VERSION 5.8 ;
BUSBITCHARS "[]" ;
DIVIDERCHAR "/" ;
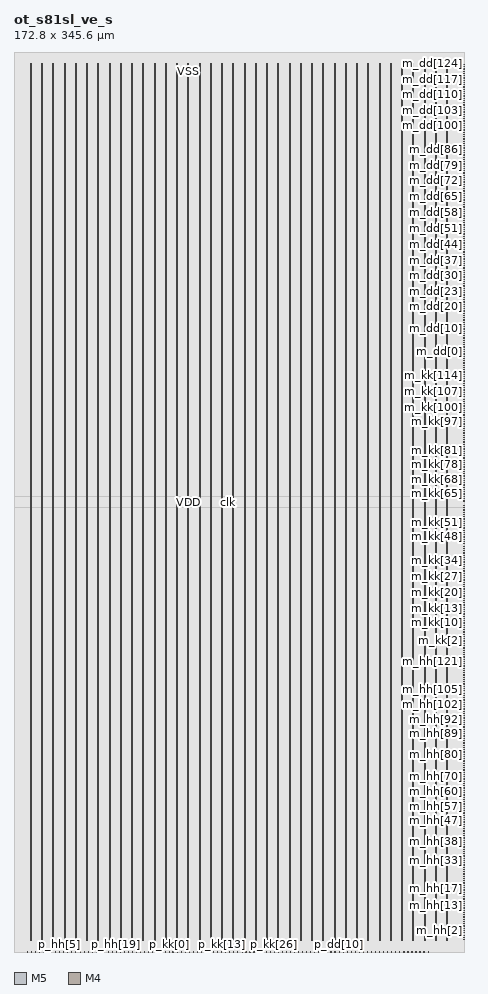
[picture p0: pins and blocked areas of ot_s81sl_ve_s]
MACRO ot_s81sl_ve_s
  CLASS BLOCK ;
  ORIGIN 0 0 ;
  SIZE 172.800 BY 345.600 ;
  PIN clk
    DIRECTION INPUT ;
    USE SIGNAL ;
    PORT
      LAYER M5 ;
        RECT 82.0680 172.5600 82.1160 173.0400 ;
    END
  END clk
  PIN fault
    DIRECTION OUTPUT ;
    USE SIGNAL ;
    PORT
      LAYER M5 ;
        RECT 159.0720 0.0000 159.0960 0.0840 ;
    END
  END fault
  PIN m_dd[0]
    DIRECTION INPUT ;
    USE SIGNAL ;
    PORT
      LAYER M4 ;
        RECT 172.716000 230.496000 172.800000 230.520000 ;
    END
  END m_dd[0]
  PIN m_dd[100]
    DIRECTION INPUT ;
    USE SIGNAL ;
    PORT
      LAYER M4 ;
        RECT 172.716000 317.376000 172.800000 317.400000 ;
    END
  END m_dd[100]
  PIN m_dd[101]
    DIRECTION INPUT ;
    USE SIGNAL ;
    PORT
      LAYER M4 ;
        RECT 172.716000 318.240000 172.800000 318.264000 ;
    END
  END m_dd[101]
  PIN m_dd[102]
    DIRECTION INPUT ;
    USE SIGNAL ;
    PORT
      LAYER M4 ;
        RECT 172.716000 319.104000 172.800000 319.128000 ;
    END
  END m_dd[102]
  PIN m_dd[103]
    DIRECTION INPUT ;
    USE SIGNAL ;
    PORT
      LAYER M4 ;
        RECT 172.716000 319.968000 172.800000 319.992000 ;
    END
  END m_dd[103]
  PIN m_dd[104]
    DIRECTION INPUT ;
    USE SIGNAL ;
    PORT
      LAYER M4 ;
        RECT 172.716000 320.832000 172.800000 320.856000 ;
    END
  END m_dd[104]
  PIN m_dd[105]
    DIRECTION INPUT ;
    USE SIGNAL ;
    PORT
      LAYER M4 ;
        RECT 172.716000 321.696000 172.800000 321.720000 ;
    END
  END m_dd[105]
  PIN m_dd[106]
    DIRECTION INPUT ;
    USE SIGNAL ;
    PORT
      LAYER M4 ;
        RECT 172.716000 322.560000 172.800000 322.584000 ;
    END
  END m_dd[106]
  PIN m_dd[107]
    DIRECTION INPUT ;
    USE SIGNAL ;
    PORT
      LAYER M4 ;
        RECT 172.716000 323.424000 172.800000 323.448000 ;
    END
  END m_dd[107]
  PIN m_dd[108]
    DIRECTION INPUT ;
    USE SIGNAL ;
    PORT
      LAYER M4 ;
        RECT 172.716000 324.288000 172.800000 324.312000 ;
    END
  END m_dd[108]
  PIN m_dd[109]
    DIRECTION INPUT ;
    USE SIGNAL ;
    PORT
      LAYER M4 ;
        RECT 172.716000 325.248000 172.800000 325.272000 ;
    END
  END m_dd[109]
  PIN m_dd[10]
    DIRECTION INPUT ;
    USE SIGNAL ;
    PORT
      LAYER M4 ;
        RECT 172.716000 239.232000 172.800000 239.256000 ;
    END
  END m_dd[10]
  PIN m_dd[110]
    DIRECTION INPUT ;
    USE SIGNAL ;
    PORT
      LAYER M4 ;
        RECT 172.716000 326.112000 172.800000 326.136000 ;
    END
  END m_dd[110]
  PIN m_dd[111]
    DIRECTION INPUT ;
    USE SIGNAL ;
    PORT
      LAYER M4 ;
        RECT 172.716000 326.976000 172.800000 327.000000 ;
    END
  END m_dd[111]
  PIN m_dd[112]
    DIRECTION INPUT ;
    USE SIGNAL ;
    PORT
      LAYER M4 ;
        RECT 172.716000 327.840000 172.800000 327.864000 ;
    END
  END m_dd[112]
  PIN m_dd[113]
    DIRECTION INPUT ;
    USE SIGNAL ;
    PORT
      LAYER M4 ;
        RECT 172.716000 328.704000 172.800000 328.728000 ;
    END
  END m_dd[113]
  PIN m_dd[114]
    DIRECTION INPUT ;
    USE SIGNAL ;
    PORT
      LAYER M4 ;
        RECT 172.716000 329.568000 172.800000 329.592000 ;
    END
  END m_dd[114]
  PIN m_dd[115]
    DIRECTION INPUT ;
    USE SIGNAL ;
    PORT
      LAYER M4 ;
        RECT 172.716000 330.432000 172.800000 330.456000 ;
    END
  END m_dd[115]
  PIN m_dd[116]
    DIRECTION INPUT ;
    USE SIGNAL ;
    PORT
      LAYER M4 ;
        RECT 172.716000 331.296000 172.800000 331.320000 ;
    END
  END m_dd[116]
  PIN m_dd[117]
    DIRECTION INPUT ;
    USE SIGNAL ;
    PORT
      LAYER M4 ;
        RECT 172.716000 332.160000 172.800000 332.184000 ;
    END
  END m_dd[117]
  PIN m_dd[118]
    DIRECTION INPUT ;
    USE SIGNAL ;
    PORT
      LAYER M4 ;
        RECT 172.716000 333.024000 172.800000 333.048000 ;
    END
  END m_dd[118]
  PIN m_dd[119]
    DIRECTION INPUT ;
    USE SIGNAL ;
    PORT
      LAYER M4 ;
        RECT 172.716000 333.888000 172.800000 333.912000 ;
    END
  END m_dd[119]
  PIN m_dd[11]
    DIRECTION INPUT ;
    USE SIGNAL ;
    PORT
      LAYER M4 ;
        RECT 172.716000 240.096000 172.800000 240.120000 ;
    END
  END m_dd[11]
  PIN m_dd[120]
    DIRECTION INPUT ;
    USE SIGNAL ;
    PORT
      LAYER M4 ;
        RECT 172.716000 334.752000 172.800000 334.776000 ;
    END
  END m_dd[120]
  PIN m_dd[121]
    DIRECTION INPUT ;
    USE SIGNAL ;
    PORT
      LAYER M4 ;
        RECT 172.716000 335.616000 172.800000 335.640000 ;
    END
  END m_dd[121]
  PIN m_dd[122]
    DIRECTION INPUT ;
    USE SIGNAL ;
    PORT
      LAYER M4 ;
        RECT 172.716000 336.480000 172.800000 336.504000 ;
    END
  END m_dd[122]
  PIN m_dd[123]
    DIRECTION INPUT ;
    USE SIGNAL ;
    PORT
      LAYER M4 ;
        RECT 172.716000 337.344000 172.800000 337.368000 ;
    END
  END m_dd[123]
  PIN m_dd[124]
    DIRECTION INPUT ;
    USE SIGNAL ;
    PORT
      LAYER M4 ;
        RECT 172.716000 338.208000 172.800000 338.232000 ;
    END
  END m_dd[124]
  PIN m_dd[125]
    DIRECTION INPUT ;
    USE SIGNAL ;
    PORT
      LAYER M4 ;
        RECT 172.716000 339.072000 172.800000 339.096000 ;
    END
  END m_dd[125]
  PIN m_dd[126]
    DIRECTION INPUT ;
    USE SIGNAL ;
    PORT
      LAYER M4 ;
        RECT 172.716000 339.936000 172.800000 339.960000 ;
    END
  END m_dd[126]
  PIN m_dd[127]
    DIRECTION INPUT ;
    USE SIGNAL ;
    PORT
      LAYER M4 ;
        RECT 172.716000 340.800000 172.800000 340.824000 ;
    END
  END m_dd[127]
  PIN m_dd[12]
    DIRECTION INPUT ;
    USE SIGNAL ;
    PORT
      LAYER M4 ;
        RECT 172.716000 240.960000 172.800000 240.984000 ;
    END
  END m_dd[12]
  PIN m_dd[13]
    DIRECTION INPUT ;
    USE SIGNAL ;
    PORT
      LAYER M4 ;
        RECT 172.716000 241.824000 172.800000 241.848000 ;
    END
  END m_dd[13]
  PIN m_dd[14]
    DIRECTION INPUT ;
    USE SIGNAL ;
    PORT
      LAYER M4 ;
        RECT 172.716000 242.688000 172.800000 242.712000 ;
    END
  END m_dd[14]
  PIN m_dd[15]
    DIRECTION INPUT ;
    USE SIGNAL ;
    PORT
      LAYER M4 ;
        RECT 172.716000 243.552000 172.800000 243.576000 ;
    END
  END m_dd[15]
  PIN m_dd[16]
    DIRECTION INPUT ;
    USE SIGNAL ;
    PORT
      LAYER M4 ;
        RECT 172.716000 244.416000 172.800000 244.440000 ;
    END
  END m_dd[16]
  PIN m_dd[17]
    DIRECTION INPUT ;
    USE SIGNAL ;
    PORT
      LAYER M4 ;
        RECT 172.716000 245.280000 172.800000 245.304000 ;
    END
  END m_dd[17]
  PIN m_dd[18]
    DIRECTION INPUT ;
    USE SIGNAL ;
    PORT
      LAYER M4 ;
        RECT 172.716000 246.144000 172.800000 246.168000 ;
    END
  END m_dd[18]
  PIN m_dd[19]
    DIRECTION INPUT ;
    USE SIGNAL ;
    PORT
      LAYER M4 ;
        RECT 172.716000 247.008000 172.800000 247.032000 ;
    END
  END m_dd[19]
  PIN m_dd[1]
    DIRECTION INPUT ;
    USE SIGNAL ;
    PORT
      LAYER M4 ;
        RECT 172.716000 231.456000 172.800000 231.480000 ;
    END
  END m_dd[1]
  PIN m_dd[20]
    DIRECTION INPUT ;
    USE SIGNAL ;
    PORT
      LAYER M4 ;
        RECT 172.716000 247.872000 172.800000 247.896000 ;
    END
  END m_dd[20]
  PIN m_dd[21]
    DIRECTION INPUT ;
    USE SIGNAL ;
    PORT
      LAYER M4 ;
        RECT 172.716000 248.736000 172.800000 248.760000 ;
    END
  END m_dd[21]
  PIN m_dd[22]
    DIRECTION INPUT ;
    USE SIGNAL ;
    PORT
      LAYER M4 ;
        RECT 172.716000 249.600000 172.800000 249.624000 ;
    END
  END m_dd[22]
  PIN m_dd[23]
    DIRECTION INPUT ;
    USE SIGNAL ;
    PORT
      LAYER M4 ;
        RECT 172.716000 250.560000 172.800000 250.584000 ;
    END
  END m_dd[23]
  PIN m_dd[24]
    DIRECTION INPUT ;
    USE SIGNAL ;
    PORT
      LAYER M4 ;
        RECT 172.716000 251.424000 172.800000 251.448000 ;
    END
  END m_dd[24]
  PIN m_dd[25]
    DIRECTION INPUT ;
    USE SIGNAL ;
    PORT
      LAYER M4 ;
        RECT 172.716000 252.288000 172.800000 252.312000 ;
    END
  END m_dd[25]
  PIN m_dd[26]
    DIRECTION INPUT ;
    USE SIGNAL ;
    PORT
      LAYER M4 ;
        RECT 172.716000 253.152000 172.800000 253.176000 ;
    END
  END m_dd[26]
  PIN m_dd[27]
    DIRECTION INPUT ;
    USE SIGNAL ;
    PORT
      LAYER M4 ;
        RECT 172.716000 254.016000 172.800000 254.040000 ;
    END
  END m_dd[27]
  PIN m_dd[28]
    DIRECTION INPUT ;
    USE SIGNAL ;
    PORT
      LAYER M4 ;
        RECT 172.716000 254.880000 172.800000 254.904000 ;
    END
  END m_dd[28]
  PIN m_dd[29]
    DIRECTION INPUT ;
    USE SIGNAL ;
    PORT
      LAYER M4 ;
        RECT 172.716000 255.744000 172.800000 255.768000 ;
    END
  END m_dd[29]
  PIN m_dd[2]
    DIRECTION INPUT ;
    USE SIGNAL ;
    PORT
      LAYER M4 ;
        RECT 172.716000 232.320000 172.800000 232.344000 ;
    END
  END m_dd[2]
  PIN m_dd[30]
    DIRECTION INPUT ;
    USE SIGNAL ;
    PORT
      LAYER M4 ;
        RECT 172.716000 256.608000 172.800000 256.632000 ;
    END
  END m_dd[30]
  PIN m_dd[31]
    DIRECTION INPUT ;
    USE SIGNAL ;
    PORT
      LAYER M4 ;
        RECT 172.716000 257.472000 172.800000 257.496000 ;
    END
  END m_dd[31]
  PIN m_dd[32]
    DIRECTION INPUT ;
    USE SIGNAL ;
    PORT
      LAYER M4 ;
        RECT 172.716000 258.336000 172.800000 258.360000 ;
    END
  END m_dd[32]
  PIN m_dd[33]
    DIRECTION INPUT ;
    USE SIGNAL ;
    PORT
      LAYER M4 ;
        RECT 172.716000 259.200000 172.800000 259.224000 ;
    END
  END m_dd[33]
  PIN m_dd[34]
    DIRECTION INPUT ;
    USE SIGNAL ;
    PORT
      LAYER M4 ;
        RECT 172.716000 260.064000 172.800000 260.088000 ;
    END
  END m_dd[34]
  PIN m_dd[35]
    DIRECTION INPUT ;
    USE SIGNAL ;
    PORT
      LAYER M4 ;
        RECT 172.716000 260.928000 172.800000 260.952000 ;
    END
  END m_dd[35]
  PIN m_dd[36]
    DIRECTION INPUT ;
    USE SIGNAL ;
    PORT
      LAYER M4 ;
        RECT 172.716000 261.792000 172.800000 261.816000 ;
    END
  END m_dd[36]
  PIN m_dd[37]
    DIRECTION INPUT ;
    USE SIGNAL ;
    PORT
      LAYER M4 ;
        RECT 172.716000 262.656000 172.800000 262.680000 ;
    END
  END m_dd[37]
  PIN m_dd[38]
    DIRECTION INPUT ;
    USE SIGNAL ;
    PORT
      LAYER M4 ;
        RECT 172.716000 263.520000 172.800000 263.544000 ;
    END
  END m_dd[38]
  PIN m_dd[39]
    DIRECTION INPUT ;
    USE SIGNAL ;
    PORT
      LAYER M4 ;
        RECT 172.716000 264.384000 172.800000 264.408000 ;
    END
  END m_dd[39]
  PIN m_dd[3]
    DIRECTION INPUT ;
    USE SIGNAL ;
    PORT
      LAYER M4 ;
        RECT 172.716000 233.184000 172.800000 233.208000 ;
    END
  END m_dd[3]
  PIN m_dd[40]
    DIRECTION INPUT ;
    USE SIGNAL ;
    PORT
      LAYER M4 ;
        RECT 172.716000 265.248000 172.800000 265.272000 ;
    END
  END m_dd[40]
  PIN m_dd[41]
    DIRECTION INPUT ;
    USE SIGNAL ;
    PORT
      LAYER M4 ;
        RECT 172.716000 266.112000 172.800000 266.136000 ;
    END
  END m_dd[41]
  PIN m_dd[42]
    DIRECTION INPUT ;
    USE SIGNAL ;
    PORT
      LAYER M4 ;
        RECT 172.716000 266.976000 172.800000 267.000000 ;
    END
  END m_dd[42]
  PIN m_dd[43]
    DIRECTION INPUT ;
    USE SIGNAL ;
    PORT
      LAYER M4 ;
        RECT 172.716000 267.840000 172.800000 267.864000 ;
    END
  END m_dd[43]
  PIN m_dd[44]
    DIRECTION INPUT ;
    USE SIGNAL ;
    PORT
      LAYER M4 ;
        RECT 172.716000 268.800000 172.800000 268.824000 ;
    END
  END m_dd[44]
  PIN m_dd[45]
    DIRECTION INPUT ;
    USE SIGNAL ;
    PORT
      LAYER M4 ;
        RECT 172.716000 269.664000 172.800000 269.688000 ;
    END
  END m_dd[45]
  PIN m_dd[46]
    DIRECTION INPUT ;
    USE SIGNAL ;
    PORT
      LAYER M4 ;
        RECT 172.716000 270.528000 172.800000 270.552000 ;
    END
  END m_dd[46]
  PIN m_dd[47]
    DIRECTION INPUT ;
    USE SIGNAL ;
    PORT
      LAYER M4 ;
        RECT 172.716000 271.392000 172.800000 271.416000 ;
    END
  END m_dd[47]
  PIN m_dd[48]
    DIRECTION INPUT ;
    USE SIGNAL ;
    PORT
      LAYER M4 ;
        RECT 172.716000 272.256000 172.800000 272.280000 ;
    END
  END m_dd[48]
  PIN m_dd[49]
    DIRECTION INPUT ;
    USE SIGNAL ;
    PORT
      LAYER M4 ;
        RECT 172.716000 273.120000 172.800000 273.144000 ;
    END
  END m_dd[49]
  PIN m_dd[4]
    DIRECTION INPUT ;
    USE SIGNAL ;
    PORT
      LAYER M4 ;
        RECT 172.716000 234.048000 172.800000 234.072000 ;
    END
  END m_dd[4]
  PIN m_dd[50]
    DIRECTION INPUT ;
    USE SIGNAL ;
    PORT
      LAYER M4 ;
        RECT 172.716000 273.984000 172.800000 274.008000 ;
    END
  END m_dd[50]
  PIN m_dd[51]
    DIRECTION INPUT ;
    USE SIGNAL ;
    PORT
      LAYER M4 ;
        RECT 172.716000 274.848000 172.800000 274.872000 ;
    END
  END m_dd[51]
  PIN m_dd[52]
    DIRECTION INPUT ;
    USE SIGNAL ;
    PORT
      LAYER M4 ;
        RECT 172.716000 275.712000 172.800000 275.736000 ;
    END
  END m_dd[52]
  PIN m_dd[53]
    DIRECTION INPUT ;
    USE SIGNAL ;
    PORT
      LAYER M4 ;
        RECT 172.716000 276.576000 172.800000 276.600000 ;
    END
  END m_dd[53]
  PIN m_dd[54]
    DIRECTION INPUT ;
    USE SIGNAL ;
    PORT
      LAYER M4 ;
        RECT 172.716000 277.440000 172.800000 277.464000 ;
    END
  END m_dd[54]
  PIN m_dd[55]
    DIRECTION INPUT ;
    USE SIGNAL ;
    PORT
      LAYER M4 ;
        RECT 172.716000 278.304000 172.800000 278.328000 ;
    END
  END m_dd[55]
  PIN m_dd[56]
    DIRECTION INPUT ;
    USE SIGNAL ;
    PORT
      LAYER M4 ;
        RECT 172.716000 279.168000 172.800000 279.192000 ;
    END
  END m_dd[56]
  PIN m_dd[57]
    DIRECTION INPUT ;
    USE SIGNAL ;
    PORT
      LAYER M4 ;
        RECT 172.716000 280.032000 172.800000 280.056000 ;
    END
  END m_dd[57]
  PIN m_dd[58]
    DIRECTION INPUT ;
    USE SIGNAL ;
    PORT
      LAYER M4 ;
        RECT 172.716000 280.896000 172.800000 280.920000 ;
    END
  END m_dd[58]
  PIN m_dd[59]
    DIRECTION INPUT ;
    USE SIGNAL ;
    PORT
      LAYER M4 ;
        RECT 172.716000 281.760000 172.800000 281.784000 ;
    END
  END m_dd[59]
  PIN m_dd[5]
    DIRECTION INPUT ;
    USE SIGNAL ;
    PORT
      LAYER M4 ;
        RECT 172.716000 234.912000 172.800000 234.936000 ;
    END
  END m_dd[5]
  PIN m_dd[60]
    DIRECTION INPUT ;
    USE SIGNAL ;
    PORT
      LAYER M4 ;
        RECT 172.716000 282.624000 172.800000 282.648000 ;
    END
  END m_dd[60]
  PIN m_dd[61]
    DIRECTION INPUT ;
    USE SIGNAL ;
    PORT
      LAYER M4 ;
        RECT 172.716000 283.488000 172.800000 283.512000 ;
    END
  END m_dd[61]
  PIN m_dd[62]
    DIRECTION INPUT ;
    USE SIGNAL ;
    PORT
      LAYER M4 ;
        RECT 172.716000 284.352000 172.800000 284.376000 ;
    END
  END m_dd[62]
  PIN m_dd[63]
    DIRECTION INPUT ;
    USE SIGNAL ;
    PORT
      LAYER M4 ;
        RECT 172.716000 285.216000 172.800000 285.240000 ;
    END
  END m_dd[63]
  PIN m_dd[64]
    DIRECTION INPUT ;
    USE SIGNAL ;
    PORT
      LAYER M4 ;
        RECT 172.716000 286.080000 172.800000 286.104000 ;
    END
  END m_dd[64]
  PIN m_dd[65]
    DIRECTION INPUT ;
    USE SIGNAL ;
    PORT
      LAYER M4 ;
        RECT 172.716000 286.944000 172.800000 286.968000 ;
    END
  END m_dd[65]
  PIN m_dd[66]
    DIRECTION INPUT ;
    USE SIGNAL ;
    PORT
      LAYER M4 ;
        RECT 172.716000 287.904000 172.800000 287.928000 ;
    END
  END m_dd[66]
  PIN m_dd[67]
    DIRECTION INPUT ;
    USE SIGNAL ;
    PORT
      LAYER M4 ;
        RECT 172.716000 288.768000 172.800000 288.792000 ;
    END
  END m_dd[67]
  PIN m_dd[68]
    DIRECTION INPUT ;
    USE SIGNAL ;
    PORT
      LAYER M4 ;
        RECT 172.716000 289.632000 172.800000 289.656000 ;
    END
  END m_dd[68]
  PIN m_dd[69]
    DIRECTION INPUT ;
    USE SIGNAL ;
    PORT
      LAYER M4 ;
        RECT 172.716000 290.496000 172.800000 290.520000 ;
    END
  END m_dd[69]
  PIN m_dd[6]
    DIRECTION INPUT ;
    USE SIGNAL ;
    PORT
      LAYER M4 ;
        RECT 172.716000 235.776000 172.800000 235.800000 ;
    END
  END m_dd[6]
  PIN m_dd[70]
    DIRECTION INPUT ;
    USE SIGNAL ;
    PORT
      LAYER M4 ;
        RECT 172.716000 291.360000 172.800000 291.384000 ;
    END
  END m_dd[70]
  PIN m_dd[71]
    DIRECTION INPUT ;
    USE SIGNAL ;
    PORT
      LAYER M4 ;
        RECT 172.716000 292.224000 172.800000 292.248000 ;
    END
  END m_dd[71]
  PIN m_dd[72]
    DIRECTION INPUT ;
    USE SIGNAL ;
    PORT
      LAYER M4 ;
        RECT 172.716000 293.088000 172.800000 293.112000 ;
    END
  END m_dd[72]
  PIN m_dd[73]
    DIRECTION INPUT ;
    USE SIGNAL ;
    PORT
      LAYER M4 ;
        RECT 172.716000 293.952000 172.800000 293.976000 ;
    END
  END m_dd[73]
  PIN m_dd[74]
    DIRECTION INPUT ;
    USE SIGNAL ;
    PORT
      LAYER M4 ;
        RECT 172.716000 294.816000 172.800000 294.840000 ;
    END
  END m_dd[74]
  PIN m_dd[75]
    DIRECTION INPUT ;
    USE SIGNAL ;
    PORT
      LAYER M4 ;
        RECT 172.716000 295.680000 172.800000 295.704000 ;
    END
  END m_dd[75]
  PIN m_dd[76]
    DIRECTION INPUT ;
    USE SIGNAL ;
    PORT
      LAYER M4 ;
        RECT 172.716000 296.544000 172.800000 296.568000 ;
    END
  END m_dd[76]
  PIN m_dd[77]
    DIRECTION INPUT ;
    USE SIGNAL ;
    PORT
      LAYER M4 ;
        RECT 172.716000 297.408000 172.800000 297.432000 ;
    END
  END m_dd[77]
  PIN m_dd[78]
    DIRECTION INPUT ;
    USE SIGNAL ;
    PORT
      LAYER M4 ;
        RECT 172.716000 298.272000 172.800000 298.296000 ;
    END
  END m_dd[78]
  PIN m_dd[79]
    DIRECTION INPUT ;
    USE SIGNAL ;
    PORT
      LAYER M4 ;
        RECT 172.716000 299.136000 172.800000 299.160000 ;
    END
  END m_dd[79]
  PIN m_dd[7]
    DIRECTION INPUT ;
    USE SIGNAL ;
    PORT
      LAYER M4 ;
        RECT 172.716000 236.640000 172.800000 236.664000 ;
    END
  END m_dd[7]
  PIN m_dd[80]
    DIRECTION INPUT ;
    USE SIGNAL ;
    PORT
      LAYER M4 ;
        RECT 172.716000 300.000000 172.800000 300.024000 ;
    END
  END m_dd[80]
  PIN m_dd[81]
    DIRECTION INPUT ;
    USE SIGNAL ;
    PORT
      LAYER M4 ;
        RECT 172.716000 300.864000 172.800000 300.888000 ;
    END
  END m_dd[81]
  PIN m_dd[82]
    DIRECTION INPUT ;
    USE SIGNAL ;
    PORT
      LAYER M4 ;
        RECT 172.716000 301.728000 172.800000 301.752000 ;
    END
  END m_dd[82]
  PIN m_dd[83]
    DIRECTION INPUT ;
    USE SIGNAL ;
    PORT
      LAYER M4 ;
        RECT 172.716000 302.592000 172.800000 302.616000 ;
    END
  END m_dd[83]
  PIN m_dd[84]
    DIRECTION INPUT ;
    USE SIGNAL ;
    PORT
      LAYER M4 ;
        RECT 172.716000 303.456000 172.800000 303.480000 ;
    END
  END m_dd[84]
  PIN m_dd[85]
    DIRECTION INPUT ;
    USE SIGNAL ;
    PORT
      LAYER M4 ;
        RECT 172.716000 304.320000 172.800000 304.344000 ;
    END
  END m_dd[85]
  PIN m_dd[86]
    DIRECTION INPUT ;
    USE SIGNAL ;
    PORT
      LAYER M4 ;
        RECT 172.716000 305.184000 172.800000 305.208000 ;
    END
  END m_dd[86]
  PIN m_dd[87]
    DIRECTION INPUT ;
    USE SIGNAL ;
    PORT
      LAYER M4 ;
        RECT 172.716000 306.048000 172.800000 306.072000 ;
    END
  END m_dd[87]
  PIN m_dd[88]
    DIRECTION INPUT ;
    USE SIGNAL ;
    PORT
      LAYER M4 ;
        RECT 172.716000 307.008000 172.800000 307.032000 ;
    END
  END m_dd[88]
  PIN m_dd[89]
    DIRECTION INPUT ;
    USE SIGNAL ;
    PORT
      LAYER M4 ;
        RECT 172.716000 307.872000 172.800000 307.896000 ;
    END
  END m_dd[89]
  PIN m_dd[8]
    DIRECTION INPUT ;
    USE SIGNAL ;
    PORT
      LAYER M4 ;
        RECT 172.716000 237.504000 172.800000 237.528000 ;
    END
  END m_dd[8]
  PIN m_dd[90]
    DIRECTION INPUT ;
    USE SIGNAL ;
    PORT
      LAYER M4 ;
        RECT 172.716000 308.736000 172.800000 308.760000 ;
    END
  END m_dd[90]
  PIN m_dd[91]
    DIRECTION INPUT ;
    USE SIGNAL ;
    PORT
      LAYER M4 ;
        RECT 172.716000 309.600000 172.800000 309.624000 ;
    END
  END m_dd[91]
  PIN m_dd[92]
    DIRECTION INPUT ;
    USE SIGNAL ;
    PORT
      LAYER M4 ;
        RECT 172.716000 310.464000 172.800000 310.488000 ;
    END
  END m_dd[92]
  PIN m_dd[93]
    DIRECTION INPUT ;
    USE SIGNAL ;
    PORT
      LAYER M4 ;
        RECT 172.716000 311.328000 172.800000 311.352000 ;
    END
  END m_dd[93]
  PIN m_dd[94]
    DIRECTION INPUT ;
    USE SIGNAL ;
    PORT
      LAYER M4 ;
        RECT 172.716000 312.192000 172.800000 312.216000 ;
    END
  END m_dd[94]
  PIN m_dd[95]
    DIRECTION INPUT ;
    USE SIGNAL ;
    PORT
      LAYER M4 ;
        RECT 172.716000 313.056000 172.800000 313.080000 ;
    END
  END m_dd[95]
  PIN m_dd[96]
    DIRECTION INPUT ;
    USE SIGNAL ;
    PORT
      LAYER M4 ;
        RECT 172.716000 313.920000 172.800000 313.944000 ;
    END
  END m_dd[96]
  PIN m_dd[97]
    DIRECTION INPUT ;
    USE SIGNAL ;
    PORT
      LAYER M4 ;
        RECT 172.716000 314.784000 172.800000 314.808000 ;
    END
  END m_dd[97]
  PIN m_dd[98]
    DIRECTION INPUT ;
    USE SIGNAL ;
    PORT
      LAYER M4 ;
        RECT 172.716000 315.648000 172.800000 315.672000 ;
    END
  END m_dd[98]
  PIN m_dd[99]
    DIRECTION INPUT ;
    USE SIGNAL ;
    PORT
      LAYER M4 ;
        RECT 172.716000 316.512000 172.800000 316.536000 ;
    END
  END m_dd[99]
  PIN m_dd[9]
    DIRECTION INPUT ;
    USE SIGNAL ;
    PORT
      LAYER M4 ;
        RECT 172.716000 238.368000 172.800000 238.392000 ;
    END
  END m_dd[9]
  PIN m_hh[0]
    DIRECTION INPUT ;
    USE SIGNAL ;
    PORT
      LAYER M4 ;
        RECT 172.716000 6.432000 172.800000 6.456000 ;
    END
  END m_hh[0]
  PIN m_hh[100]
    DIRECTION INPUT ;
    USE SIGNAL ;
    PORT
      LAYER M4 ;
        RECT 172.716000 93.312000 172.800000 93.336000 ;
    END
  END m_hh[100]
  PIN m_hh[101]
    DIRECTION INPUT ;
    USE SIGNAL ;
    PORT
      LAYER M4 ;
        RECT 172.716000 94.176000 172.800000 94.200000 ;
    END
  END m_hh[101]
  PIN m_hh[102]
    DIRECTION INPUT ;
    USE SIGNAL ;
    PORT
      LAYER M4 ;
        RECT 172.716000 95.040000 172.800000 95.064000 ;
    END
  END m_hh[102]
  PIN m_hh[103]
    DIRECTION INPUT ;
    USE SIGNAL ;
    PORT
      LAYER M4 ;
        RECT 172.716000 95.904000 172.800000 95.928000 ;
    END
  END m_hh[103]
  PIN m_hh[104]
    DIRECTION INPUT ;
    USE SIGNAL ;
    PORT
      LAYER M4 ;
        RECT 172.716000 96.768000 172.800000 96.792000 ;
    END
  END m_hh[104]
  PIN m_hh[105]
    DIRECTION INPUT ;
    USE SIGNAL ;
    PORT
      LAYER M4 ;
        RECT 172.716000 97.632000 172.800000 97.656000 ;
    END
  END m_hh[105]
  PIN m_hh[106]
    DIRECTION INPUT ;
    USE SIGNAL ;
    PORT
      LAYER M4 ;
        RECT 172.716000 98.496000 172.800000 98.520000 ;
    END
  END m_hh[106]
  PIN m_hh[107]
    DIRECTION INPUT ;
    USE SIGNAL ;
    PORT
      LAYER M4 ;
        RECT 172.716000 99.360000 172.800000 99.384000 ;
    END
  END m_hh[107]
  PIN m_hh[108]
    DIRECTION INPUT ;
    USE SIGNAL ;
    PORT
      LAYER M4 ;
        RECT 172.716000 100.320000 172.800000 100.344000 ;
    END
  END m_hh[108]
  PIN m_hh[109]
    DIRECTION INPUT ;
    USE SIGNAL ;
    PORT
      LAYER M4 ;
        RECT 172.716000 101.184000 172.800000 101.208000 ;
    END
  END m_hh[109]
  PIN m_hh[10]
    DIRECTION INPUT ;
    USE SIGNAL ;
    PORT
      LAYER M4 ;
        RECT 172.716000 15.168000 172.800000 15.192000 ;
    END
  END m_hh[10]
  PIN m_hh[110]
    DIRECTION INPUT ;
    USE SIGNAL ;
    PORT
      LAYER M4 ;
        RECT 172.716000 102.048000 172.800000 102.072000 ;
    END
  END m_hh[110]
  PIN m_hh[111]
    DIRECTION INPUT ;
    USE SIGNAL ;
    PORT
      LAYER M4 ;
        RECT 172.716000 102.912000 172.800000 102.936000 ;
    END
  END m_hh[111]
  PIN m_hh[112]
    DIRECTION INPUT ;
    USE SIGNAL ;
    PORT
      LAYER M4 ;
        RECT 172.716000 103.776000 172.800000 103.800000 ;
    END
  END m_hh[112]
  PIN m_hh[113]
    DIRECTION INPUT ;
    USE SIGNAL ;
    PORT
      LAYER M4 ;
        RECT 172.716000 104.640000 172.800000 104.664000 ;
    END
  END m_hh[113]
  PIN m_hh[114]
    DIRECTION INPUT ;
    USE SIGNAL ;
    PORT
      LAYER M4 ;
        RECT 172.716000 105.504000 172.800000 105.528000 ;
    END
  END m_hh[114]
  PIN m_hh[115]
    DIRECTION INPUT ;
    USE SIGNAL ;
    PORT
      LAYER M4 ;
        RECT 172.716000 106.368000 172.800000 106.392000 ;
    END
  END m_hh[115]
  PIN m_hh[116]
    DIRECTION INPUT ;
    USE SIGNAL ;
    PORT
      LAYER M4 ;
        RECT 172.716000 107.232000 172.800000 107.256000 ;
    END
  END m_hh[116]
  PIN m_hh[117]
    DIRECTION INPUT ;
    USE SIGNAL ;
    PORT
      LAYER M4 ;
        RECT 172.716000 108.096000 172.800000 108.120000 ;
    END
  END m_hh[117]
  PIN m_hh[118]
    DIRECTION INPUT ;
    USE SIGNAL ;
    PORT
      LAYER M4 ;
        RECT 172.716000 108.960000 172.800000 108.984000 ;
    END
  END m_hh[118]
  PIN m_hh[119]
    DIRECTION INPUT ;
    USE SIGNAL ;
    PORT
      LAYER M4 ;
        RECT 172.716000 109.824000 172.800000 109.848000 ;
    END
  END m_hh[119]
  PIN m_hh[11]
    DIRECTION INPUT ;
    USE SIGNAL ;
    PORT
      LAYER M4 ;
        RECT 172.716000 16.032000 172.800000 16.056000 ;
    END
  END m_hh[11]
  PIN m_hh[120]
    DIRECTION INPUT ;
    USE SIGNAL ;
    PORT
      LAYER M4 ;
        RECT 172.716000 110.688000 172.800000 110.712000 ;
    END
  END m_hh[120]
  PIN m_hh[121]
    DIRECTION INPUT ;
    USE SIGNAL ;
    PORT
      LAYER M4 ;
        RECT 172.716000 111.552000 172.800000 111.576000 ;
    END
  END m_hh[121]
  PIN m_hh[122]
    DIRECTION INPUT ;
    USE SIGNAL ;
    PORT
      LAYER M4 ;
        RECT 172.716000 112.416000 172.800000 112.440000 ;
    END
  END m_hh[122]
  PIN m_hh[123]
    DIRECTION INPUT ;
    USE SIGNAL ;
    PORT
      LAYER M4 ;
        RECT 172.716000 113.280000 172.800000 113.304000 ;
    END
  END m_hh[123]
  PIN m_hh[124]
    DIRECTION INPUT ;
    USE SIGNAL ;
    PORT
      LAYER M4 ;
        RECT 172.716000 114.144000 172.800000 114.168000 ;
    END
  END m_hh[124]
  PIN m_hh[125]
    DIRECTION INPUT ;
    USE SIGNAL ;
    PORT
      LAYER M4 ;
        RECT 172.716000 115.008000 172.800000 115.032000 ;
    END
  END m_hh[125]
  PIN m_hh[126]
    DIRECTION INPUT ;
    USE SIGNAL ;
    PORT
      LAYER M4 ;
        RECT 172.716000 115.872000 172.800000 115.896000 ;
    END
  END m_hh[126]
  PIN m_hh[127]
    DIRECTION INPUT ;
    USE SIGNAL ;
    PORT
      LAYER M4 ;
        RECT 172.716000 116.736000 172.800000 116.760000 ;
    END
  END m_hh[127]
  PIN m_hh[12]
    DIRECTION INPUT ;
    USE SIGNAL ;
    PORT
      LAYER M4 ;
        RECT 172.716000 16.896000 172.800000 16.920000 ;
    END
  END m_hh[12]
  PIN m_hh[13]
    DIRECTION INPUT ;
    USE SIGNAL ;
    PORT
      LAYER M4 ;
        RECT 172.716000 17.760000 172.800000 17.784000 ;
    END
  END m_hh[13]
  PIN m_hh[14]
    DIRECTION INPUT ;
    USE SIGNAL ;
    PORT
      LAYER M4 ;
        RECT 172.716000 18.624000 172.800000 18.648000 ;
    END
  END m_hh[14]
  PIN m_hh[15]
    DIRECTION INPUT ;
    USE SIGNAL ;
    PORT
      LAYER M4 ;
        RECT 172.716000 19.488000 172.800000 19.512000 ;
    END
  END m_hh[15]
  PIN m_hh[16]
    DIRECTION INPUT ;
    USE SIGNAL ;
    PORT
      LAYER M4 ;
        RECT 172.716000 20.352000 172.800000 20.376000 ;
    END
  END m_hh[16]
  PIN m_hh[17]
    DIRECTION INPUT ;
    USE SIGNAL ;
    PORT
      LAYER M4 ;
        RECT 172.716000 21.216000 172.800000 21.240000 ;
    END
  END m_hh[17]
  PIN m_hh[18]
    DIRECTION INPUT ;
    USE SIGNAL ;
    PORT
      LAYER M4 ;
        RECT 172.716000 22.080000 172.800000 22.104000 ;
    END
  END m_hh[18]
  PIN m_hh[19]
    DIRECTION INPUT ;
    USE SIGNAL ;
    PORT
      LAYER M4 ;
        RECT 172.716000 22.944000 172.800000 22.968000 ;
    END
  END m_hh[19]
  PIN m_hh[1]
    DIRECTION INPUT ;
    USE SIGNAL ;
    PORT
      LAYER M4 ;
        RECT 172.716000 7.392000 172.800000 7.416000 ;
    END
  END m_hh[1]
  PIN m_hh[20]
    DIRECTION INPUT ;
    USE SIGNAL ;
    PORT
      LAYER M4 ;
        RECT 172.716000 23.808000 172.800000 23.832000 ;
    END
  END m_hh[20]
  PIN m_hh[21]
    DIRECTION INPUT ;
    USE SIGNAL ;
    PORT
      LAYER M4 ;
        RECT 172.716000 24.672000 172.800000 24.696000 ;
    END
  END m_hh[21]
  PIN m_hh[22]
    DIRECTION INPUT ;
    USE SIGNAL ;
    PORT
      LAYER M4 ;
        RECT 172.716000 25.632000 172.800000 25.656000 ;
    END
  END m_hh[22]
  PIN m_hh[23]
    DIRECTION INPUT ;
    USE SIGNAL ;
    PORT
      LAYER M4 ;
        RECT 172.716000 26.496000 172.800000 26.520000 ;
    END
  END m_hh[23]
  PIN m_hh[24]
    DIRECTION INPUT ;
    USE SIGNAL ;
    PORT
      LAYER M4 ;
        RECT 172.716000 27.360000 172.800000 27.384000 ;
    END
  END m_hh[24]
  PIN m_hh[25]
    DIRECTION INPUT ;
    USE SIGNAL ;
    PORT
      LAYER M4 ;
        RECT 172.716000 28.224000 172.800000 28.248000 ;
    END
  END m_hh[25]
  PIN m_hh[26]
    DIRECTION INPUT ;
    USE SIGNAL ;
    PORT
      LAYER M4 ;
        RECT 172.716000 29.088000 172.800000 29.112000 ;
    END
  END m_hh[26]
  PIN m_hh[27]
    DIRECTION INPUT ;
    USE SIGNAL ;
    PORT
      LAYER M4 ;
        RECT 172.716000 29.952000 172.800000 29.976000 ;
    END
  END m_hh[27]
  PIN m_hh[28]
    DIRECTION INPUT ;
    USE SIGNAL ;
    PORT
      LAYER M4 ;
        RECT 172.716000 30.816000 172.800000 30.840000 ;
    END
  END m_hh[28]
  PIN m_hh[29]
    DIRECTION INPUT ;
    USE SIGNAL ;
    PORT
      LAYER M4 ;
        RECT 172.716000 31.680000 172.800000 31.704000 ;
    END
  END m_hh[29]
  PIN m_hh[2]
    DIRECTION INPUT ;
    USE SIGNAL ;
    PORT
      LAYER M4 ;
        RECT 172.716000 8.256000 172.800000 8.280000 ;
    END
  END m_hh[2]
  PIN m_hh[30]
    DIRECTION INPUT ;
    USE SIGNAL ;
    PORT
      LAYER M4 ;
        RECT 172.716000 32.544000 172.800000 32.568000 ;
    END
  END m_hh[30]
  PIN m_hh[31]
    DIRECTION INPUT ;
    USE SIGNAL ;
    PORT
      LAYER M4 ;
        RECT 172.716000 33.408000 172.800000 33.432000 ;
    END
  END m_hh[31]
  PIN m_hh[32]
    DIRECTION INPUT ;
    USE SIGNAL ;
    PORT
      LAYER M4 ;
        RECT 172.716000 34.272000 172.800000 34.296000 ;
    END
  END m_hh[32]
  PIN m_hh[33]
    DIRECTION INPUT ;
    USE SIGNAL ;
    PORT
      LAYER M4 ;
        RECT 172.716000 35.136000 172.800000 35.160000 ;
    END
  END m_hh[33]
  PIN m_hh[34]
    DIRECTION INPUT ;
    USE SIGNAL ;
    PORT
      LAYER M4 ;
        RECT 172.716000 36.000000 172.800000 36.024000 ;
    END
  END m_hh[34]
  PIN m_hh[35]
    DIRECTION INPUT ;
    USE SIGNAL ;
    PORT
      LAYER M4 ;
        RECT 172.716000 36.864000 172.800000 36.888000 ;
    END
  END m_hh[35]
  PIN m_hh[36]
    DIRECTION INPUT ;
    USE SIGNAL ;
    PORT
      LAYER M4 ;
        RECT 172.716000 37.728000 172.800000 37.752000 ;
    END
  END m_hh[36]
  PIN m_hh[37]
    DIRECTION INPUT ;
    USE SIGNAL ;
    PORT
      LAYER M4 ;
        RECT 172.716000 38.592000 172.800000 38.616000 ;
    END
  END m_hh[37]
  PIN m_hh[38]
    DIRECTION INPUT ;
    USE SIGNAL ;
    PORT
      LAYER M4 ;
        RECT 172.716000 39.456000 172.800000 39.480000 ;
    END
  END m_hh[38]
  PIN m_hh[39]
    DIRECTION INPUT ;
    USE SIGNAL ;
    PORT
      LAYER M4 ;
        RECT 172.716000 40.320000 172.800000 40.344000 ;
    END
  END m_hh[39]
  PIN m_hh[3]
    DIRECTION INPUT ;
    USE SIGNAL ;
    PORT
      LAYER M4 ;
        RECT 172.716000 9.120000 172.800000 9.144000 ;
    END
  END m_hh[3]
  PIN m_hh[40]
    DIRECTION INPUT ;
    USE SIGNAL ;
    PORT
      LAYER M4 ;
        RECT 172.716000 41.184000 172.800000 41.208000 ;
    END
  END m_hh[40]
  PIN m_hh[41]
    DIRECTION INPUT ;
    USE SIGNAL ;
    PORT
      LAYER M4 ;
        RECT 172.716000 42.048000 172.800000 42.072000 ;
    END
  END m_hh[41]
  PIN m_hh[42]
    DIRECTION INPUT ;
    USE SIGNAL ;
    PORT
      LAYER M4 ;
        RECT 172.716000 42.912000 172.800000 42.936000 ;
    END
  END m_hh[42]
  PIN m_hh[43]
    DIRECTION INPUT ;
    USE SIGNAL ;
    PORT
      LAYER M4 ;
        RECT 172.716000 43.776000 172.800000 43.800000 ;
    END
  END m_hh[43]
  PIN m_hh[44]
    DIRECTION INPUT ;
    USE SIGNAL ;
    PORT
      LAYER M4 ;
        RECT 172.716000 44.736000 172.800000 44.760000 ;
    END
  END m_hh[44]
  PIN m_hh[45]
    DIRECTION INPUT ;
    USE SIGNAL ;
    PORT
      LAYER M4 ;
        RECT 172.716000 45.600000 172.800000 45.624000 ;
    END
  END m_hh[45]
  PIN m_hh[46]
    DIRECTION INPUT ;
    USE SIGNAL ;
    PORT
      LAYER M4 ;
        RECT 172.716000 46.464000 172.800000 46.488000 ;
    END
  END m_hh[46]
  PIN m_hh[47]
    DIRECTION INPUT ;
    USE SIGNAL ;
    PORT
      LAYER M4 ;
        RECT 172.716000 47.328000 172.800000 47.352000 ;
    END
  END m_hh[47]
  PIN m_hh[48]
    DIRECTION INPUT ;
    USE SIGNAL ;
    PORT
      LAYER M4 ;
        RECT 172.716000 48.192000 172.800000 48.216000 ;
    END
  END m_hh[48]
  PIN m_hh[49]
    DIRECTION INPUT ;
    USE SIGNAL ;
    PORT
      LAYER M4 ;
        RECT 172.716000 49.056000 172.800000 49.080000 ;
    END
  END m_hh[49]
  PIN m_hh[4]
    DIRECTION INPUT ;
    USE SIGNAL ;
    PORT
      LAYER M4 ;
        RECT 172.716000 9.984000 172.800000 10.008000 ;
    END
  END m_hh[4]
  PIN m_hh[50]
    DIRECTION INPUT ;
    USE SIGNAL ;
    PORT
      LAYER M4 ;
        RECT 172.716000 49.920000 172.800000 49.944000 ;
    END
  END m_hh[50]
  PIN m_hh[51]
    DIRECTION INPUT ;
    USE SIGNAL ;
    PORT
      LAYER M4 ;
        RECT 172.716000 50.784000 172.800000 50.808000 ;
    END
  END m_hh[51]
  PIN m_hh[52]
    DIRECTION INPUT ;
    USE SIGNAL ;
    PORT
      LAYER M4 ;
        RECT 172.716000 51.648000 172.800000 51.672000 ;
    END
  END m_hh[52]
  PIN m_hh[53]
    DIRECTION INPUT ;
    USE SIGNAL ;
    PORT
      LAYER M4 ;
        RECT 172.716000 52.512000 172.800000 52.536000 ;
    END
  END m_hh[53]
  PIN m_hh[54]
    DIRECTION INPUT ;
    USE SIGNAL ;
    PORT
      LAYER M4 ;
        RECT 172.716000 53.376000 172.800000 53.400000 ;
    END
  END m_hh[54]
  PIN m_hh[55]
    DIRECTION INPUT ;
    USE SIGNAL ;
    PORT
      LAYER M4 ;
        RECT 172.716000 54.240000 172.800000 54.264000 ;
    END
  END m_hh[55]
  PIN m_hh[56]
    DIRECTION INPUT ;
    USE SIGNAL ;
    PORT
      LAYER M4 ;
        RECT 172.716000 55.104000 172.800000 55.128000 ;
    END
  END m_hh[56]
  PIN m_hh[57]
    DIRECTION INPUT ;
    USE SIGNAL ;
    PORT
      LAYER M4 ;
        RECT 172.716000 55.968000 172.800000 55.992000 ;
    END
  END m_hh[57]
  PIN m_hh[58]
    DIRECTION INPUT ;
    USE SIGNAL ;
    PORT
      LAYER M4 ;
        RECT 172.716000 56.832000 172.800000 56.856000 ;
    END
  END m_hh[58]
  PIN m_hh[59]
    DIRECTION INPUT ;
    USE SIGNAL ;
    PORT
      LAYER M4 ;
        RECT 172.716000 57.696000 172.800000 57.720000 ;
    END
  END m_hh[59]
  PIN m_hh[5]
    DIRECTION INPUT ;
    USE SIGNAL ;
    PORT
      LAYER M4 ;
        RECT 172.716000 10.848000 172.800000 10.872000 ;
    END
  END m_hh[5]
  PIN m_hh[60]
    DIRECTION INPUT ;
    USE SIGNAL ;
    PORT
      LAYER M4 ;
        RECT 172.716000 58.560000 172.800000 58.584000 ;
    END
  END m_hh[60]
  PIN m_hh[61]
    DIRECTION INPUT ;
    USE SIGNAL ;
    PORT
      LAYER M4 ;
        RECT 172.716000 59.424000 172.800000 59.448000 ;
    END
  END m_hh[61]
  PIN m_hh[62]
    DIRECTION INPUT ;
    USE SIGNAL ;
    PORT
      LAYER M4 ;
        RECT 172.716000 60.288000 172.800000 60.312000 ;
    END
  END m_hh[62]
  PIN m_hh[63]
    DIRECTION INPUT ;
    USE SIGNAL ;
    PORT
      LAYER M4 ;
        RECT 172.716000 61.152000 172.800000 61.176000 ;
    END
  END m_hh[63]
  PIN m_hh[64]
    DIRECTION INPUT ;
    USE SIGNAL ;
    PORT
      LAYER M4 ;
        RECT 172.716000 62.016000 172.800000 62.040000 ;
    END
  END m_hh[64]
  PIN m_hh[65]
    DIRECTION INPUT ;
    USE SIGNAL ;
    PORT
      LAYER M4 ;
        RECT 172.716000 62.976000 172.800000 63.000000 ;
    END
  END m_hh[65]
  PIN m_hh[66]
    DIRECTION INPUT ;
    USE SIGNAL ;
    PORT
      LAYER M4 ;
        RECT 172.716000 63.840000 172.800000 63.864000 ;
    END
  END m_hh[66]
  PIN m_hh[67]
    DIRECTION INPUT ;
    USE SIGNAL ;
    PORT
      LAYER M4 ;
        RECT 172.716000 64.704000 172.800000 64.728000 ;
    END
  END m_hh[67]
  PIN m_hh[68]
    DIRECTION INPUT ;
    USE SIGNAL ;
    PORT
      LAYER M4 ;
        RECT 172.716000 65.568000 172.800000 65.592000 ;
    END
  END m_hh[68]
  PIN m_hh[69]
    DIRECTION INPUT ;
    USE SIGNAL ;
    PORT
      LAYER M4 ;
        RECT 172.716000 66.432000 172.800000 66.456000 ;
    END
  END m_hh[69]
  PIN m_hh[6]
    DIRECTION INPUT ;
    USE SIGNAL ;
    PORT
      LAYER M4 ;
        RECT 172.716000 11.712000 172.800000 11.736000 ;
    END
  END m_hh[6]
  PIN m_hh[70]
    DIRECTION INPUT ;
    USE SIGNAL ;
    PORT
      LAYER M4 ;
        RECT 172.716000 67.296000 172.800000 67.320000 ;
    END
  END m_hh[70]
  PIN m_hh[71]
    DIRECTION INPUT ;
    USE SIGNAL ;
    PORT
      LAYER M4 ;
        RECT 172.716000 68.160000 172.800000 68.184000 ;
    END
  END m_hh[71]
  PIN m_hh[72]
    DIRECTION INPUT ;
    USE SIGNAL ;
    PORT
      LAYER M4 ;
        RECT 172.716000 69.024000 172.800000 69.048000 ;
    END
  END m_hh[72]
  PIN m_hh[73]
    DIRECTION INPUT ;
    USE SIGNAL ;
    PORT
      LAYER M4 ;
        RECT 172.716000 69.888000 172.800000 69.912000 ;
    END
  END m_hh[73]
  PIN m_hh[74]
    DIRECTION INPUT ;
    USE SIGNAL ;
    PORT
      LAYER M4 ;
        RECT 172.716000 70.752000 172.800000 70.776000 ;
    END
  END m_hh[74]
  PIN m_hh[75]
    DIRECTION INPUT ;
    USE SIGNAL ;
    PORT
      LAYER M4 ;
        RECT 172.716000 71.616000 172.800000 71.640000 ;
    END
  END m_hh[75]
  PIN m_hh[76]
    DIRECTION INPUT ;
    USE SIGNAL ;
    PORT
      LAYER M4 ;
        RECT 172.716000 72.480000 172.800000 72.504000 ;
    END
  END m_hh[76]
  PIN m_hh[77]
    DIRECTION INPUT ;
    USE SIGNAL ;
    PORT
      LAYER M4 ;
        RECT 172.716000 73.344000 172.800000 73.368000 ;
    END
  END m_hh[77]
  PIN m_hh[78]
    DIRECTION INPUT ;
    USE SIGNAL ;
    PORT
      LAYER M4 ;
        RECT 172.716000 74.208000 172.800000 74.232000 ;
    END
  END m_hh[78]
  PIN m_hh[79]
    DIRECTION INPUT ;
    USE SIGNAL ;
    PORT
      LAYER M4 ;
        RECT 172.716000 75.072000 172.800000 75.096000 ;
    END
  END m_hh[79]
  PIN m_hh[7]
    DIRECTION INPUT ;
    USE SIGNAL ;
    PORT
      LAYER M4 ;
        RECT 172.716000 12.576000 172.800000 12.600000 ;
    END
  END m_hh[7]
  PIN m_hh[80]
    DIRECTION INPUT ;
    USE SIGNAL ;
    PORT
      LAYER M4 ;
        RECT 172.716000 75.936000 172.800000 75.960000 ;
    END
  END m_hh[80]
  PIN m_hh[81]
    DIRECTION INPUT ;
    USE SIGNAL ;
    PORT
      LAYER M4 ;
        RECT 172.716000 76.800000 172.800000 76.824000 ;
    END
  END m_hh[81]
  PIN m_hh[82]
    DIRECTION INPUT ;
    USE SIGNAL ;
    PORT
      LAYER M4 ;
        RECT 172.716000 77.664000 172.800000 77.688000 ;
    END
  END m_hh[82]
  PIN m_hh[83]
    DIRECTION INPUT ;
    USE SIGNAL ;
    PORT
      LAYER M4 ;
        RECT 172.716000 78.528000 172.800000 78.552000 ;
    END
  END m_hh[83]
  PIN m_hh[84]
    DIRECTION INPUT ;
    USE SIGNAL ;
    PORT
      LAYER M4 ;
        RECT 172.716000 79.392000 172.800000 79.416000 ;
    END
  END m_hh[84]
  PIN m_hh[85]
    DIRECTION INPUT ;
    USE SIGNAL ;
    PORT
      LAYER M4 ;
        RECT 172.716000 80.256000 172.800000 80.280000 ;
    END
  END m_hh[85]
  PIN m_hh[86]
    DIRECTION INPUT ;
    USE SIGNAL ;
    PORT
      LAYER M4 ;
        RECT 172.716000 81.120000 172.800000 81.144000 ;
    END
  END m_hh[86]
  PIN m_hh[87]
    DIRECTION INPUT ;
    USE SIGNAL ;
    PORT
      LAYER M4 ;
        RECT 172.716000 82.080000 172.800000 82.104000 ;
    END
  END m_hh[87]
  PIN m_hh[88]
    DIRECTION INPUT ;
    USE SIGNAL ;
    PORT
      LAYER M4 ;
        RECT 172.716000 82.944000 172.800000 82.968000 ;
    END
  END m_hh[88]
  PIN m_hh[89]
    DIRECTION INPUT ;
    USE SIGNAL ;
    PORT
      LAYER M4 ;
        RECT 172.716000 83.808000 172.800000 83.832000 ;
    END
  END m_hh[89]
  PIN m_hh[8]
    DIRECTION INPUT ;
    USE SIGNAL ;
    PORT
      LAYER M4 ;
        RECT 172.716000 13.440000 172.800000 13.464000 ;
    END
  END m_hh[8]
  PIN m_hh[90]
    DIRECTION INPUT ;
    USE SIGNAL ;
    PORT
      LAYER M4 ;
        RECT 172.716000 84.672000 172.800000 84.696000 ;
    END
  END m_hh[90]
  PIN m_hh[91]
    DIRECTION INPUT ;
    USE SIGNAL ;
    PORT
      LAYER M4 ;
        RECT 172.716000 85.536000 172.800000 85.560000 ;
    END
  END m_hh[91]
  PIN m_hh[92]
    DIRECTION INPUT ;
    USE SIGNAL ;
    PORT
      LAYER M4 ;
        RECT 172.716000 86.400000 172.800000 86.424000 ;
    END
  END m_hh[92]
  PIN m_hh[93]
    DIRECTION INPUT ;
    USE SIGNAL ;
    PORT
      LAYER M4 ;
        RECT 172.716000 87.264000 172.800000 87.288000 ;
    END
  END m_hh[93]
  PIN m_hh[94]
    DIRECTION INPUT ;
    USE SIGNAL ;
    PORT
      LAYER M4 ;
        RECT 172.716000 88.128000 172.800000 88.152000 ;
    END
  END m_hh[94]
  PIN m_hh[95]
    DIRECTION INPUT ;
    USE SIGNAL ;
    PORT
      LAYER M4 ;
        RECT 172.716000 88.992000 172.800000 89.016000 ;
    END
  END m_hh[95]
  PIN m_hh[96]
    DIRECTION INPUT ;
    USE SIGNAL ;
    PORT
      LAYER M4 ;
        RECT 172.716000 89.856000 172.800000 89.880000 ;
    END
  END m_hh[96]
  PIN m_hh[97]
    DIRECTION INPUT ;
    USE SIGNAL ;
    PORT
      LAYER M4 ;
        RECT 172.716000 90.720000 172.800000 90.744000 ;
    END
  END m_hh[97]
  PIN m_hh[98]
    DIRECTION INPUT ;
    USE SIGNAL ;
    PORT
      LAYER M4 ;
        RECT 172.716000 91.584000 172.800000 91.608000 ;
    END
  END m_hh[98]
  PIN m_hh[99]
    DIRECTION INPUT ;
    USE SIGNAL ;
    PORT
      LAYER M4 ;
        RECT 172.716000 92.448000 172.800000 92.472000 ;
    END
  END m_hh[99]
  PIN m_hh[9]
    DIRECTION INPUT ;
    USE SIGNAL ;
    PORT
      LAYER M4 ;
        RECT 172.716000 14.304000 172.800000 14.328000 ;
    END
  END m_hh[9]
  PIN m_kk[0]
    DIRECTION INPUT ;
    USE SIGNAL ;
    PORT
      LAYER M4 ;
        RECT 172.716000 117.600000 172.800000 117.624000 ;
    END
  END m_kk[0]
  PIN m_kk[100]
    DIRECTION INPUT ;
    USE SIGNAL ;
    PORT
      LAYER M4 ;
        RECT 172.716000 206.208000 172.800000 206.232000 ;
    END
  END m_kk[100]
  PIN m_kk[101]
    DIRECTION INPUT ;
    USE SIGNAL ;
    PORT
      LAYER M4 ;
        RECT 172.716000 207.072000 172.800000 207.096000 ;
    END
  END m_kk[101]
  PIN m_kk[102]
    DIRECTION INPUT ;
    USE SIGNAL ;
    PORT
      LAYER M4 ;
        RECT 172.716000 207.936000 172.800000 207.960000 ;
    END
  END m_kk[102]
  PIN m_kk[103]
    DIRECTION INPUT ;
    USE SIGNAL ;
    PORT
      LAYER M4 ;
        RECT 172.716000 208.800000 172.800000 208.824000 ;
    END
  END m_kk[103]
  PIN m_kk[104]
    DIRECTION INPUT ;
    USE SIGNAL ;
    PORT
      LAYER M4 ;
        RECT 172.716000 209.664000 172.800000 209.688000 ;
    END
  END m_kk[104]
  PIN m_kk[105]
    DIRECTION INPUT ;
    USE SIGNAL ;
    PORT
      LAYER M4 ;
        RECT 172.716000 210.528000 172.800000 210.552000 ;
    END
  END m_kk[105]
  PIN m_kk[106]
    DIRECTION INPUT ;
    USE SIGNAL ;
    PORT
      LAYER M4 ;
        RECT 172.716000 211.392000 172.800000 211.416000 ;
    END
  END m_kk[106]
  PIN m_kk[107]
    DIRECTION INPUT ;
    USE SIGNAL ;
    PORT
      LAYER M4 ;
        RECT 172.716000 212.256000 172.800000 212.280000 ;
    END
  END m_kk[107]
  PIN m_kk[108]
    DIRECTION INPUT ;
    USE SIGNAL ;
    PORT
      LAYER M4 ;
        RECT 172.716000 213.216000 172.800000 213.240000 ;
    END
  END m_kk[108]
  PIN m_kk[109]
    DIRECTION INPUT ;
    USE SIGNAL ;
    PORT
      LAYER M4 ;
        RECT 172.716000 214.080000 172.800000 214.104000 ;
    END
  END m_kk[109]
  PIN m_kk[10]
    DIRECTION INPUT ;
    USE SIGNAL ;
    PORT
      LAYER M4 ;
        RECT 172.716000 126.336000 172.800000 126.360000 ;
    END
  END m_kk[10]
  PIN m_kk[110]
    DIRECTION INPUT ;
    USE SIGNAL ;
    PORT
      LAYER M4 ;
        RECT 172.716000 214.944000 172.800000 214.968000 ;
    END
  END m_kk[110]
  PIN m_kk[111]
    DIRECTION INPUT ;
    USE SIGNAL ;
    PORT
      LAYER M4 ;
        RECT 172.716000 215.808000 172.800000 215.832000 ;
    END
  END m_kk[111]
  PIN m_kk[112]
    DIRECTION INPUT ;
    USE SIGNAL ;
    PORT
      LAYER M4 ;
        RECT 172.716000 216.672000 172.800000 216.696000 ;
    END
  END m_kk[112]
  PIN m_kk[113]
    DIRECTION INPUT ;
    USE SIGNAL ;
    PORT
      LAYER M4 ;
        RECT 172.716000 217.536000 172.800000 217.560000 ;
    END
  END m_kk[113]
  PIN m_kk[114]
    DIRECTION INPUT ;
    USE SIGNAL ;
    PORT
      LAYER M4 ;
        RECT 172.716000 218.400000 172.800000 218.424000 ;
    END
  END m_kk[114]
  PIN m_kk[115]
    DIRECTION INPUT ;
    USE SIGNAL ;
    PORT
      LAYER M4 ;
        RECT 172.716000 219.264000 172.800000 219.288000 ;
    END
  END m_kk[115]
  PIN m_kk[116]
    DIRECTION INPUT ;
    USE SIGNAL ;
    PORT
      LAYER M4 ;
        RECT 172.716000 220.128000 172.800000 220.152000 ;
    END
  END m_kk[116]
  PIN m_kk[117]
    DIRECTION INPUT ;
    USE SIGNAL ;
    PORT
      LAYER M4 ;
        RECT 172.716000 220.992000 172.800000 221.016000 ;
    END
  END m_kk[117]
  PIN m_kk[118]
    DIRECTION INPUT ;
    USE SIGNAL ;
    PORT
      LAYER M4 ;
        RECT 172.716000 221.856000 172.800000 221.880000 ;
    END
  END m_kk[118]
  PIN m_kk[119]
    DIRECTION INPUT ;
    USE SIGNAL ;
    PORT
      LAYER M4 ;
        RECT 172.716000 222.720000 172.800000 222.744000 ;
    END
  END m_kk[119]
  PIN m_kk[11]
    DIRECTION INPUT ;
    USE SIGNAL ;
    PORT
      LAYER M4 ;
        RECT 172.716000 127.200000 172.800000 127.224000 ;
    END
  END m_kk[11]
  PIN m_kk[120]
    DIRECTION INPUT ;
    USE SIGNAL ;
    PORT
      LAYER M4 ;
        RECT 172.716000 223.584000 172.800000 223.608000 ;
    END
  END m_kk[120]
  PIN m_kk[121]
    DIRECTION INPUT ;
    USE SIGNAL ;
    PORT
      LAYER M4 ;
        RECT 172.716000 224.448000 172.800000 224.472000 ;
    END
  END m_kk[121]
  PIN m_kk[122]
    DIRECTION INPUT ;
    USE SIGNAL ;
    PORT
      LAYER M4 ;
        RECT 172.716000 225.312000 172.800000 225.336000 ;
    END
  END m_kk[122]
  PIN m_kk[123]
    DIRECTION INPUT ;
    USE SIGNAL ;
    PORT
      LAYER M4 ;
        RECT 172.716000 226.176000 172.800000 226.200000 ;
    END
  END m_kk[123]
  PIN m_kk[124]
    DIRECTION INPUT ;
    USE SIGNAL ;
    PORT
      LAYER M4 ;
        RECT 172.716000 227.040000 172.800000 227.064000 ;
    END
  END m_kk[124]
  PIN m_kk[125]
    DIRECTION INPUT ;
    USE SIGNAL ;
    PORT
      LAYER M4 ;
        RECT 172.716000 227.904000 172.800000 227.928000 ;
    END
  END m_kk[125]
  PIN m_kk[126]
    DIRECTION INPUT ;
    USE SIGNAL ;
    PORT
      LAYER M4 ;
        RECT 172.716000 228.768000 172.800000 228.792000 ;
    END
  END m_kk[126]
  PIN m_kk[127]
    DIRECTION INPUT ;
    USE SIGNAL ;
    PORT
      LAYER M4 ;
        RECT 172.716000 229.632000 172.800000 229.656000 ;
    END
  END m_kk[127]
  PIN m_kk[12]
    DIRECTION INPUT ;
    USE SIGNAL ;
    PORT
      LAYER M4 ;
        RECT 172.716000 128.064000 172.800000 128.088000 ;
    END
  END m_kk[12]
  PIN m_kk[13]
    DIRECTION INPUT ;
    USE SIGNAL ;
    PORT
      LAYER M4 ;
        RECT 172.716000 128.928000 172.800000 128.952000 ;
    END
  END m_kk[13]
  PIN m_kk[14]
    DIRECTION INPUT ;
    USE SIGNAL ;
    PORT
      LAYER M4 ;
        RECT 172.716000 129.792000 172.800000 129.816000 ;
    END
  END m_kk[14]
  PIN m_kk[15]
    DIRECTION INPUT ;
    USE SIGNAL ;
    PORT
      LAYER M4 ;
        RECT 172.716000 130.656000 172.800000 130.680000 ;
    END
  END m_kk[15]
  PIN m_kk[16]
    DIRECTION INPUT ;
    USE SIGNAL ;
    PORT
      LAYER M4 ;
        RECT 172.716000 131.520000 172.800000 131.544000 ;
    END
  END m_kk[16]
  PIN m_kk[17]
    DIRECTION INPUT ;
    USE SIGNAL ;
    PORT
      LAYER M4 ;
        RECT 172.716000 132.384000 172.800000 132.408000 ;
    END
  END m_kk[17]
  PIN m_kk[18]
    DIRECTION INPUT ;
    USE SIGNAL ;
    PORT
      LAYER M4 ;
        RECT 172.716000 133.248000 172.800000 133.272000 ;
    END
  END m_kk[18]
  PIN m_kk[19]
    DIRECTION INPUT ;
    USE SIGNAL ;
    PORT
      LAYER M4 ;
        RECT 172.716000 134.112000 172.800000 134.136000 ;
    END
  END m_kk[19]
  PIN m_kk[1]
    DIRECTION INPUT ;
    USE SIGNAL ;
    PORT
      LAYER M4 ;
        RECT 172.716000 118.464000 172.800000 118.488000 ;
    END
  END m_kk[1]
  PIN m_kk[20]
    DIRECTION INPUT ;
    USE SIGNAL ;
    PORT
      LAYER M4 ;
        RECT 172.716000 134.976000 172.800000 135.000000 ;
    END
  END m_kk[20]
  PIN m_kk[21]
    DIRECTION INPUT ;
    USE SIGNAL ;
    PORT
      LAYER M4 ;
        RECT 172.716000 135.840000 172.800000 135.864000 ;
    END
  END m_kk[21]
  PIN m_kk[22]
    DIRECTION INPUT ;
    USE SIGNAL ;
    PORT
      LAYER M4 ;
        RECT 172.716000 136.704000 172.800000 136.728000 ;
    END
  END m_kk[22]
  PIN m_kk[23]
    DIRECTION INPUT ;
    USE SIGNAL ;
    PORT
      LAYER M4 ;
        RECT 172.716000 137.568000 172.800000 137.592000 ;
    END
  END m_kk[23]
  PIN m_kk[24]
    DIRECTION INPUT ;
    USE SIGNAL ;
    PORT
      LAYER M4 ;
        RECT 172.716000 138.528000 172.800000 138.552000 ;
    END
  END m_kk[24]
  PIN m_kk[25]
    DIRECTION INPUT ;
    USE SIGNAL ;
    PORT
      LAYER M4 ;
        RECT 172.716000 139.392000 172.800000 139.416000 ;
    END
  END m_kk[25]
  PIN m_kk[26]
    DIRECTION INPUT ;
    USE SIGNAL ;
    PORT
      LAYER M4 ;
        RECT 172.716000 140.256000 172.800000 140.280000 ;
    END
  END m_kk[26]
  PIN m_kk[27]
    DIRECTION INPUT ;
    USE SIGNAL ;
    PORT
      LAYER M4 ;
        RECT 172.716000 141.120000 172.800000 141.144000 ;
    END
  END m_kk[27]
  PIN m_kk[28]
    DIRECTION INPUT ;
    USE SIGNAL ;
    PORT
      LAYER M4 ;
        RECT 172.716000 141.984000 172.800000 142.008000 ;
    END
  END m_kk[28]
  PIN m_kk[29]
    DIRECTION INPUT ;
    USE SIGNAL ;
    PORT
      LAYER M4 ;
        RECT 172.716000 142.848000 172.800000 142.872000 ;
    END
  END m_kk[29]
  PIN m_kk[2]
    DIRECTION INPUT ;
    USE SIGNAL ;
    PORT
      LAYER M4 ;
        RECT 172.716000 119.424000 172.800000 119.448000 ;
    END
  END m_kk[2]
  PIN m_kk[30]
    DIRECTION INPUT ;
    USE SIGNAL ;
    PORT
      LAYER M4 ;
        RECT 172.716000 143.712000 172.800000 143.736000 ;
    END
  END m_kk[30]
  PIN m_kk[31]
    DIRECTION INPUT ;
    USE SIGNAL ;
    PORT
      LAYER M4 ;
        RECT 172.716000 144.576000 172.800000 144.600000 ;
    END
  END m_kk[31]
  PIN m_kk[32]
    DIRECTION INPUT ;
    USE SIGNAL ;
    PORT
      LAYER M4 ;
        RECT 172.716000 145.440000 172.800000 145.464000 ;
    END
  END m_kk[32]
  PIN m_kk[33]
    DIRECTION INPUT ;
    USE SIGNAL ;
    PORT
      LAYER M4 ;
        RECT 172.716000 146.304000 172.800000 146.328000 ;
    END
  END m_kk[33]
  PIN m_kk[34]
    DIRECTION INPUT ;
    USE SIGNAL ;
    PORT
      LAYER M4 ;
        RECT 172.716000 147.168000 172.800000 147.192000 ;
    END
  END m_kk[34]
  PIN m_kk[35]
    DIRECTION INPUT ;
    USE SIGNAL ;
    PORT
      LAYER M4 ;
        RECT 172.716000 148.032000 172.800000 148.056000 ;
    END
  END m_kk[35]
  PIN m_kk[36]
    DIRECTION INPUT ;
    USE SIGNAL ;
    PORT
      LAYER M4 ;
        RECT 172.716000 148.896000 172.800000 148.920000 ;
    END
  END m_kk[36]
  PIN m_kk[37]
    DIRECTION INPUT ;
    USE SIGNAL ;
    PORT
      LAYER M4 ;
        RECT 172.716000 149.760000 172.800000 149.784000 ;
    END
  END m_kk[37]
  PIN m_kk[38]
    DIRECTION INPUT ;
    USE SIGNAL ;
    PORT
      LAYER M4 ;
        RECT 172.716000 150.624000 172.800000 150.648000 ;
    END
  END m_kk[38]
  PIN m_kk[39]
    DIRECTION INPUT ;
    USE SIGNAL ;
    PORT
      LAYER M4 ;
        RECT 172.716000 151.488000 172.800000 151.512000 ;
    END
  END m_kk[39]
  PIN m_kk[3]
    DIRECTION INPUT ;
    USE SIGNAL ;
    PORT
      LAYER M4 ;
        RECT 172.716000 120.288000 172.800000 120.312000 ;
    END
  END m_kk[3]
  PIN m_kk[40]
    DIRECTION INPUT ;
    USE SIGNAL ;
    PORT
      LAYER M4 ;
        RECT 172.716000 152.352000 172.800000 152.376000 ;
    END
  END m_kk[40]
  PIN m_kk[41]
    DIRECTION INPUT ;
    USE SIGNAL ;
    PORT
      LAYER M4 ;
        RECT 172.716000 153.216000 172.800000 153.240000 ;
    END
  END m_kk[41]
  PIN m_kk[42]
    DIRECTION INPUT ;
    USE SIGNAL ;
    PORT
      LAYER M4 ;
        RECT 172.716000 154.080000 172.800000 154.104000 ;
    END
  END m_kk[42]
  PIN m_kk[43]
    DIRECTION INPUT ;
    USE SIGNAL ;
    PORT
      LAYER M4 ;
        RECT 172.716000 154.944000 172.800000 154.968000 ;
    END
  END m_kk[43]
  PIN m_kk[44]
    DIRECTION INPUT ;
    USE SIGNAL ;
    PORT
      LAYER M4 ;
        RECT 172.716000 155.808000 172.800000 155.832000 ;
    END
  END m_kk[44]
  PIN m_kk[45]
    DIRECTION INPUT ;
    USE SIGNAL ;
    PORT
      LAYER M4 ;
        RECT 172.716000 156.768000 172.800000 156.792000 ;
    END
  END m_kk[45]
  PIN m_kk[46]
    DIRECTION INPUT ;
    USE SIGNAL ;
    PORT
      LAYER M4 ;
        RECT 172.716000 157.632000 172.800000 157.656000 ;
    END
  END m_kk[46]
  PIN m_kk[47]
    DIRECTION INPUT ;
    USE SIGNAL ;
    PORT
      LAYER M4 ;
        RECT 172.716000 158.496000 172.800000 158.520000 ;
    END
  END m_kk[47]
  PIN m_kk[48]
    DIRECTION INPUT ;
    USE SIGNAL ;
    PORT
      LAYER M4 ;
        RECT 172.716000 159.360000 172.800000 159.384000 ;
    END
  END m_kk[48]
  PIN m_kk[49]
    DIRECTION INPUT ;
    USE SIGNAL ;
    PORT
      LAYER M4 ;
        RECT 172.716000 160.224000 172.800000 160.248000 ;
    END
  END m_kk[49]
  PIN m_kk[4]
    DIRECTION INPUT ;
    USE SIGNAL ;
    PORT
      LAYER M4 ;
        RECT 172.716000 121.152000 172.800000 121.176000 ;
    END
  END m_kk[4]
  PIN m_kk[50]
    DIRECTION INPUT ;
    USE SIGNAL ;
    PORT
      LAYER M4 ;
        RECT 172.716000 161.088000 172.800000 161.112000 ;
    END
  END m_kk[50]
  PIN m_kk[51]
    DIRECTION INPUT ;
    USE SIGNAL ;
    PORT
      LAYER M4 ;
        RECT 172.716000 161.952000 172.800000 161.976000 ;
    END
  END m_kk[51]
  PIN m_kk[52]
    DIRECTION INPUT ;
    USE SIGNAL ;
    PORT
      LAYER M4 ;
        RECT 172.716000 162.816000 172.800000 162.840000 ;
    END
  END m_kk[52]
  PIN m_kk[53]
    DIRECTION INPUT ;
    USE SIGNAL ;
    PORT
      LAYER M4 ;
        RECT 172.716000 163.680000 172.800000 163.704000 ;
    END
  END m_kk[53]
  PIN m_kk[54]
    DIRECTION INPUT ;
    USE SIGNAL ;
    PORT
      LAYER M4 ;
        RECT 172.716000 164.544000 172.800000 164.568000 ;
    END
  END m_kk[54]
  PIN m_kk[55]
    DIRECTION INPUT ;
    USE SIGNAL ;
    PORT
      LAYER M4 ;
        RECT 172.716000 165.408000 172.800000 165.432000 ;
    END
  END m_kk[55]
  PIN m_kk[56]
    DIRECTION INPUT ;
    USE SIGNAL ;
    PORT
      LAYER M4 ;
        RECT 172.716000 166.272000 172.800000 166.296000 ;
    END
  END m_kk[56]
  PIN m_kk[57]
    DIRECTION INPUT ;
    USE SIGNAL ;
    PORT
      LAYER M4 ;
        RECT 172.716000 167.136000 172.800000 167.160000 ;
    END
  END m_kk[57]
  PIN m_kk[58]
    DIRECTION INPUT ;
    USE SIGNAL ;
    PORT
      LAYER M4 ;
        RECT 172.716000 168.000000 172.800000 168.024000 ;
    END
  END m_kk[58]
  PIN m_kk[59]
    DIRECTION INPUT ;
    USE SIGNAL ;
    PORT
      LAYER M4 ;
        RECT 172.716000 168.864000 172.800000 168.888000 ;
    END
  END m_kk[59]
  PIN m_kk[5]
    DIRECTION INPUT ;
    USE SIGNAL ;
    PORT
      LAYER M4 ;
        RECT 172.716000 122.016000 172.800000 122.040000 ;
    END
  END m_kk[5]
  PIN m_kk[60]
    DIRECTION INPUT ;
    USE SIGNAL ;
    PORT
      LAYER M4 ;
        RECT 172.716000 169.728000 172.800000 169.752000 ;
    END
  END m_kk[60]
  PIN m_kk[61]
    DIRECTION INPUT ;
    USE SIGNAL ;
    PORT
      LAYER M4 ;
        RECT 172.716000 170.592000 172.800000 170.616000 ;
    END
  END m_kk[61]
  PIN m_kk[62]
    DIRECTION INPUT ;
    USE SIGNAL ;
    PORT
      LAYER M4 ;
        RECT 172.716000 171.456000 172.800000 171.480000 ;
    END
  END m_kk[62]
  PIN m_kk[63]
    DIRECTION INPUT ;
    USE SIGNAL ;
    PORT
      LAYER M4 ;
        RECT 172.716000 174.048000 172.800000 174.072000 ;
    END
  END m_kk[63]
  PIN m_kk[64]
    DIRECTION INPUT ;
    USE SIGNAL ;
    PORT
      LAYER M4 ;
        RECT 172.716000 174.912000 172.800000 174.936000 ;
    END
  END m_kk[64]
  PIN m_kk[65]
    DIRECTION INPUT ;
    USE SIGNAL ;
    PORT
      LAYER M4 ;
        RECT 172.716000 175.872000 172.800000 175.896000 ;
    END
  END m_kk[65]
  PIN m_kk[66]
    DIRECTION INPUT ;
    USE SIGNAL ;
    PORT
      LAYER M4 ;
        RECT 172.716000 176.736000 172.800000 176.760000 ;
    END
  END m_kk[66]
  PIN m_kk[67]
    DIRECTION INPUT ;
    USE SIGNAL ;
    PORT
      LAYER M4 ;
        RECT 172.716000 177.600000 172.800000 177.624000 ;
    END
  END m_kk[67]
  PIN m_kk[68]
    DIRECTION INPUT ;
    USE SIGNAL ;
    PORT
      LAYER M4 ;
        RECT 172.716000 178.464000 172.800000 178.488000 ;
    END
  END m_kk[68]
  PIN m_kk[69]
    DIRECTION INPUT ;
    USE SIGNAL ;
    PORT
      LAYER M4 ;
        RECT 172.716000 179.328000 172.800000 179.352000 ;
    END
  END m_kk[69]
  PIN m_kk[6]
    DIRECTION INPUT ;
    USE SIGNAL ;
    PORT
      LAYER M4 ;
        RECT 172.716000 122.880000 172.800000 122.904000 ;
    END
  END m_kk[6]
  PIN m_kk[70]
    DIRECTION INPUT ;
    USE SIGNAL ;
    PORT
      LAYER M4 ;
        RECT 172.716000 180.192000 172.800000 180.216000 ;
    END
  END m_kk[70]
  PIN m_kk[71]
    DIRECTION INPUT ;
    USE SIGNAL ;
    PORT
      LAYER M4 ;
        RECT 172.716000 181.056000 172.800000 181.080000 ;
    END
  END m_kk[71]
  PIN m_kk[72]
    DIRECTION INPUT ;
    USE SIGNAL ;
    PORT
      LAYER M4 ;
        RECT 172.716000 181.920000 172.800000 181.944000 ;
    END
  END m_kk[72]
  PIN m_kk[73]
    DIRECTION INPUT ;
    USE SIGNAL ;
    PORT
      LAYER M4 ;
        RECT 172.716000 182.784000 172.800000 182.808000 ;
    END
  END m_kk[73]
  PIN m_kk[74]
    DIRECTION INPUT ;
    USE SIGNAL ;
    PORT
      LAYER M4 ;
        RECT 172.716000 183.648000 172.800000 183.672000 ;
    END
  END m_kk[74]
  PIN m_kk[75]
    DIRECTION INPUT ;
    USE SIGNAL ;
    PORT
      LAYER M4 ;
        RECT 172.716000 184.512000 172.800000 184.536000 ;
    END
  END m_kk[75]
  PIN m_kk[76]
    DIRECTION INPUT ;
    USE SIGNAL ;
    PORT
      LAYER M4 ;
        RECT 172.716000 185.376000 172.800000 185.400000 ;
    END
  END m_kk[76]
  PIN m_kk[77]
    DIRECTION INPUT ;
    USE SIGNAL ;
    PORT
      LAYER M4 ;
        RECT 172.716000 186.240000 172.800000 186.264000 ;
    END
  END m_kk[77]
  PIN m_kk[78]
    DIRECTION INPUT ;
    USE SIGNAL ;
    PORT
      LAYER M4 ;
        RECT 172.716000 187.104000 172.800000 187.128000 ;
    END
  END m_kk[78]
  PIN m_kk[79]
    DIRECTION INPUT ;
    USE SIGNAL ;
    PORT
      LAYER M4 ;
        RECT 172.716000 187.968000 172.800000 187.992000 ;
    END
  END m_kk[79]
  PIN m_kk[7]
    DIRECTION INPUT ;
    USE SIGNAL ;
    PORT
      LAYER M4 ;
        RECT 172.716000 123.744000 172.800000 123.768000 ;
    END
  END m_kk[7]
  PIN m_kk[80]
    DIRECTION INPUT ;
    USE SIGNAL ;
    PORT
      LAYER M4 ;
        RECT 172.716000 188.832000 172.800000 188.856000 ;
    END
  END m_kk[80]
  PIN m_kk[81]
    DIRECTION INPUT ;
    USE SIGNAL ;
    PORT
      LAYER M4 ;
        RECT 172.716000 189.696000 172.800000 189.720000 ;
    END
  END m_kk[81]
  PIN m_kk[82]
    DIRECTION INPUT ;
    USE SIGNAL ;
    PORT
      LAYER M4 ;
        RECT 172.716000 190.560000 172.800000 190.584000 ;
    END
  END m_kk[82]
  PIN m_kk[83]
    DIRECTION INPUT ;
    USE SIGNAL ;
    PORT
      LAYER M4 ;
        RECT 172.716000 191.424000 172.800000 191.448000 ;
    END
  END m_kk[83]
  PIN m_kk[84]
    DIRECTION INPUT ;
    USE SIGNAL ;
    PORT
      LAYER M4 ;
        RECT 172.716000 192.288000 172.800000 192.312000 ;
    END
  END m_kk[84]
  PIN m_kk[85]
    DIRECTION INPUT ;
    USE SIGNAL ;
    PORT
      LAYER M4 ;
        RECT 172.716000 193.152000 172.800000 193.176000 ;
    END
  END m_kk[85]
  PIN m_kk[86]
    DIRECTION INPUT ;
    USE SIGNAL ;
    PORT
      LAYER M4 ;
        RECT 172.716000 194.112000 172.800000 194.136000 ;
    END
  END m_kk[86]
  PIN m_kk[87]
    DIRECTION INPUT ;
    USE SIGNAL ;
    PORT
      LAYER M4 ;
        RECT 172.716000 194.976000 172.800000 195.000000 ;
    END
  END m_kk[87]
  PIN m_kk[88]
    DIRECTION INPUT ;
    USE SIGNAL ;
    PORT
      LAYER M4 ;
        RECT 172.716000 195.840000 172.800000 195.864000 ;
    END
  END m_kk[88]
  PIN m_kk[89]
    DIRECTION INPUT ;
    USE SIGNAL ;
    PORT
      LAYER M4 ;
        RECT 172.716000 196.704000 172.800000 196.728000 ;
    END
  END m_kk[89]
  PIN m_kk[8]
    DIRECTION INPUT ;
    USE SIGNAL ;
    PORT
      LAYER M4 ;
        RECT 172.716000 124.608000 172.800000 124.632000 ;
    END
  END m_kk[8]
  PIN m_kk[90]
    DIRECTION INPUT ;
    USE SIGNAL ;
    PORT
      LAYER M4 ;
        RECT 172.716000 197.568000 172.800000 197.592000 ;
    END
  END m_kk[90]
  PIN m_kk[91]
    DIRECTION INPUT ;
    USE SIGNAL ;
    PORT
      LAYER M4 ;
        RECT 172.716000 198.432000 172.800000 198.456000 ;
    END
  END m_kk[91]
  PIN m_kk[92]
    DIRECTION INPUT ;
    USE SIGNAL ;
    PORT
      LAYER M4 ;
        RECT 172.716000 199.296000 172.800000 199.320000 ;
    END
  END m_kk[92]
  PIN m_kk[93]
    DIRECTION INPUT ;
    USE SIGNAL ;
    PORT
      LAYER M4 ;
        RECT 172.716000 200.160000 172.800000 200.184000 ;
    END
  END m_kk[93]
  PIN m_kk[94]
    DIRECTION INPUT ;
    USE SIGNAL ;
    PORT
      LAYER M4 ;
        RECT 172.716000 201.024000 172.800000 201.048000 ;
    END
  END m_kk[94]
  PIN m_kk[95]
    DIRECTION INPUT ;
    USE SIGNAL ;
    PORT
      LAYER M4 ;
        RECT 172.716000 201.888000 172.800000 201.912000 ;
    END
  END m_kk[95]
  PIN m_kk[96]
    DIRECTION INPUT ;
    USE SIGNAL ;
    PORT
      LAYER M4 ;
        RECT 172.716000 202.752000 172.800000 202.776000 ;
    END
  END m_kk[96]
  PIN m_kk[97]
    DIRECTION INPUT ;
    USE SIGNAL ;
    PORT
      LAYER M4 ;
        RECT 172.716000 203.616000 172.800000 203.640000 ;
    END
  END m_kk[97]
  PIN m_kk[98]
    DIRECTION INPUT ;
    USE SIGNAL ;
    PORT
      LAYER M4 ;
        RECT 172.716000 204.480000 172.800000 204.504000 ;
    END
  END m_kk[98]
  PIN m_kk[99]
    DIRECTION INPUT ;
    USE SIGNAL ;
    PORT
      LAYER M4 ;
        RECT 172.716000 205.344000 172.800000 205.368000 ;
    END
  END m_kk[99]
  PIN m_kk[9]
    DIRECTION INPUT ;
    USE SIGNAL ;
    PORT
      LAYER M4 ;
        RECT 172.716000 125.472000 172.800000 125.496000 ;
    END
  END m_kk[9]
  PIN m_pre
    DIRECTION INPUT ;
    USE SIGNAL ;
    PORT
      LAYER M4 ;
        RECT 172.716000 5.568000 172.800000 5.592000 ;
    END
  END m_pre
  PIN m_v
    DIRECTION INPUT ;
    USE SIGNAL ;
    PORT
      LAYER M4 ;
        RECT 172.716000 4.704000 172.800000 4.728000 ;
    END
  END m_v
  PIN p_c[0]
    DIRECTION OUTPUT ;
    USE SIGNAL ;
    PORT
      LAYER M5 ;
        RECT 6.6240 0.0000 6.6480 0.0840 ;
    END
  END p_c[0]
  PIN p_c[1]
    DIRECTION OUTPUT ;
    USE SIGNAL ;
    PORT
      LAYER M5 ;
        RECT 8.1600 0.0000 8.1840 0.0840 ;
    END
  END p_c[1]
  PIN p_dd[0]
    DIRECTION OUTPUT ;
    USE SIGNAL ;
    PORT
      LAYER M5 ;
        RECT 109.2480 0.0000 109.2720 0.0840 ;
    END
  END p_dd[0]
  PIN p_dd[10]
    DIRECTION OUTPUT ;
    USE SIGNAL ;
    PORT
      LAYER M5 ;
        RECT 124.8000 0.0000 124.8240 0.0840 ;
    END
  END p_dd[10]
  PIN p_dd[11]
    DIRECTION OUTPUT ;
    USE SIGNAL ;
    PORT
      LAYER M5 ;
        RECT 126.3360 0.0000 126.3600 0.0840 ;
    END
  END p_dd[11]
  PIN p_dd[12]
    DIRECTION OUTPUT ;
    USE SIGNAL ;
    PORT
      LAYER M5 ;
        RECT 127.9680 0.0000 127.9920 0.0840 ;
    END
  END p_dd[12]
  PIN p_dd[13]
    DIRECTION OUTPUT ;
    USE SIGNAL ;
    PORT
      LAYER M5 ;
        RECT 129.5040 0.0000 129.5280 0.0840 ;
    END
  END p_dd[13]
  PIN p_dd[14]
    DIRECTION OUTPUT ;
    USE SIGNAL ;
    PORT
      LAYER M5 ;
        RECT 131.0400 0.0000 131.0640 0.0840 ;
    END
  END p_dd[14]
  PIN p_dd[15]
    DIRECTION OUTPUT ;
    USE SIGNAL ;
    PORT
      LAYER M5 ;
        RECT 132.5760 0.0000 132.6000 0.0840 ;
    END
  END p_dd[15]
  PIN p_dd[16]
    DIRECTION OUTPUT ;
    USE SIGNAL ;
    PORT
      LAYER M5 ;
        RECT 134.2080 0.0000 134.2320 0.0840 ;
    END
  END p_dd[16]
  PIN p_dd[17]
    DIRECTION OUTPUT ;
    USE SIGNAL ;
    PORT
      LAYER M5 ;
        RECT 135.7440 0.0000 135.7680 0.0840 ;
    END
  END p_dd[17]
  PIN p_dd[18]
    DIRECTION OUTPUT ;
    USE SIGNAL ;
    PORT
      LAYER M5 ;
        RECT 137.2800 0.0000 137.3040 0.0840 ;
    END
  END p_dd[18]
  PIN p_dd[19]
    DIRECTION OUTPUT ;
    USE SIGNAL ;
    PORT
      LAYER M5 ;
        RECT 138.8160 0.0000 138.8400 0.0840 ;
    END
  END p_dd[19]
  PIN p_dd[1]
    DIRECTION OUTPUT ;
    USE SIGNAL ;
    PORT
      LAYER M5 ;
        RECT 110.7840 0.0000 110.8080 0.0840 ;
    END
  END p_dd[1]
  PIN p_dd[20]
    DIRECTION OUTPUT ;
    USE SIGNAL ;
    PORT
      LAYER M5 ;
        RECT 140.3520 0.0000 140.3760 0.0840 ;
    END
  END p_dd[20]
  PIN p_dd[21]
    DIRECTION OUTPUT ;
    USE SIGNAL ;
    PORT
      LAYER M5 ;
        RECT 141.8880 0.0000 141.9120 0.0840 ;
    END
  END p_dd[21]
  PIN p_dd[22]
    DIRECTION OUTPUT ;
    USE SIGNAL ;
    PORT
      LAYER M5 ;
        RECT 143.5200 0.0000 143.5440 0.0840 ;
    END
  END p_dd[22]
  PIN p_dd[23]
    DIRECTION OUTPUT ;
    USE SIGNAL ;
    PORT
      LAYER M5 ;
        RECT 145.0560 0.0000 145.0800 0.0840 ;
    END
  END p_dd[23]
  PIN p_dd[24]
    DIRECTION OUTPUT ;
    USE SIGNAL ;
    PORT
      LAYER M5 ;
        RECT 146.5920 0.0000 146.6160 0.0840 ;
    END
  END p_dd[24]
  PIN p_dd[25]
    DIRECTION OUTPUT ;
    USE SIGNAL ;
    PORT
      LAYER M5 ;
        RECT 148.1280 0.0000 148.1520 0.0840 ;
    END
  END p_dd[25]
  PIN p_dd[26]
    DIRECTION OUTPUT ;
    USE SIGNAL ;
    PORT
      LAYER M5 ;
        RECT 149.7600 0.0000 149.7840 0.0840 ;
    END
  END p_dd[26]
  PIN p_dd[27]
    DIRECTION OUTPUT ;
    USE SIGNAL ;
    PORT
      LAYER M5 ;
        RECT 151.2960 0.0000 151.3200 0.0840 ;
    END
  END p_dd[27]
  PIN p_dd[28]
    DIRECTION OUTPUT ;
    USE SIGNAL ;
    PORT
      LAYER M5 ;
        RECT 152.8320 0.0000 152.8560 0.0840 ;
    END
  END p_dd[28]
  PIN p_dd[29]
    DIRECTION OUTPUT ;
    USE SIGNAL ;
    PORT
      LAYER M5 ;
        RECT 154.3680 0.0000 154.3920 0.0840 ;
    END
  END p_dd[29]
  PIN p_dd[2]
    DIRECTION OUTPUT ;
    USE SIGNAL ;
    PORT
      LAYER M5 ;
        RECT 112.4160 0.0000 112.4400 0.0840 ;
    END
  END p_dd[2]
  PIN p_dd[30]
    DIRECTION OUTPUT ;
    USE SIGNAL ;
    PORT
      LAYER M5 ;
        RECT 155.9040 0.0000 155.9280 0.0840 ;
    END
  END p_dd[30]
  PIN p_dd[31]
    DIRECTION OUTPUT ;
    USE SIGNAL ;
    PORT
      LAYER M5 ;
        RECT 157.4400 0.0000 157.4640 0.0840 ;
    END
  END p_dd[31]
  PIN p_dd[3]
    DIRECTION OUTPUT ;
    USE SIGNAL ;
    PORT
      LAYER M5 ;
        RECT 113.9520 0.0000 113.9760 0.0840 ;
    END
  END p_dd[3]
  PIN p_dd[4]
    DIRECTION OUTPUT ;
    USE SIGNAL ;
    PORT
      LAYER M5 ;
        RECT 115.4880 0.0000 115.5120 0.0840 ;
    END
  END p_dd[4]
  PIN p_dd[5]
    DIRECTION OUTPUT ;
    USE SIGNAL ;
    PORT
      LAYER M5 ;
        RECT 117.0240 0.0000 117.0480 0.0840 ;
    END
  END p_dd[5]
  PIN p_dd[6]
    DIRECTION OUTPUT ;
    USE SIGNAL ;
    PORT
      LAYER M5 ;
        RECT 118.6560 0.0000 118.6800 0.0840 ;
    END
  END p_dd[6]
  PIN p_dd[7]
    DIRECTION OUTPUT ;
    USE SIGNAL ;
    PORT
      LAYER M5 ;
        RECT 120.1920 0.0000 120.2160 0.0840 ;
    END
  END p_dd[7]
  PIN p_dd[8]
    DIRECTION OUTPUT ;
    USE SIGNAL ;
    PORT
      LAYER M5 ;
        RECT 121.7280 0.0000 121.7520 0.0840 ;
    END
  END p_dd[8]
  PIN p_dd[9]
    DIRECTION OUTPUT ;
    USE SIGNAL ;
    PORT
      LAYER M5 ;
        RECT 123.2640 0.0000 123.2880 0.0840 ;
    END
  END p_dd[9]
  PIN p_hh[0]
    DIRECTION OUTPUT ;
    USE SIGNAL ;
    PORT
      LAYER M5 ;
        RECT 9.7920 0.0000 9.8160 0.0840 ;
    END
  END p_hh[0]
  PIN p_hh[10]
    DIRECTION OUTPUT ;
    USE SIGNAL ;
    PORT
      LAYER M5 ;
        RECT 25.3440 0.0000 25.3680 0.0840 ;
    END
  END p_hh[10]
  PIN p_hh[11]
    DIRECTION OUTPUT ;
    USE SIGNAL ;
    PORT
      LAYER M5 ;
        RECT 26.8800 0.0000 26.9040 0.0840 ;
    END
  END p_hh[11]
  PIN p_hh[12]
    DIRECTION OUTPUT ;
    USE SIGNAL ;
    PORT
      LAYER M5 ;
        RECT 28.4160 0.0000 28.4400 0.0840 ;
    END
  END p_hh[12]
  PIN p_hh[13]
    DIRECTION OUTPUT ;
    USE SIGNAL ;
    PORT
      LAYER M5 ;
        RECT 29.9520 0.0000 29.9760 0.0840 ;
    END
  END p_hh[13]
  PIN p_hh[14]
    DIRECTION OUTPUT ;
    USE SIGNAL ;
    PORT
      LAYER M5 ;
        RECT 31.4880 0.0000 31.5120 0.0840 ;
    END
  END p_hh[14]
  PIN p_hh[15]
    DIRECTION OUTPUT ;
    USE SIGNAL ;
    PORT
      LAYER M5 ;
        RECT 33.0240 0.0000 33.0480 0.0840 ;
    END
  END p_hh[15]
  PIN p_hh[16]
    DIRECTION OUTPUT ;
    USE SIGNAL ;
    PORT
      LAYER M5 ;
        RECT 34.6560 0.0000 34.6800 0.0840 ;
    END
  END p_hh[16]
  PIN p_hh[17]
    DIRECTION OUTPUT ;
    USE SIGNAL ;
    PORT
      LAYER M5 ;
        RECT 36.1920 0.0000 36.2160 0.0840 ;
    END
  END p_hh[17]
  PIN p_hh[18]
    DIRECTION OUTPUT ;
    USE SIGNAL ;
    PORT
      LAYER M5 ;
        RECT 37.7280 0.0000 37.7520 0.0840 ;
    END
  END p_hh[18]
  PIN p_hh[19]
    DIRECTION OUTPUT ;
    USE SIGNAL ;
    PORT
      LAYER M5 ;
        RECT 39.2640 0.0000 39.2880 0.0840 ;
    END
  END p_hh[19]
  PIN p_hh[1]
    DIRECTION OUTPUT ;
    USE SIGNAL ;
    PORT
      LAYER M5 ;
        RECT 11.3280 0.0000 11.3520 0.0840 ;
    END
  END p_hh[1]
  PIN p_hh[20]
    DIRECTION OUTPUT ;
    USE SIGNAL ;
    PORT
      LAYER M5 ;
        RECT 40.8960 0.0000 40.9200 0.0840 ;
    END
  END p_hh[20]
  PIN p_hh[21]
    DIRECTION OUTPUT ;
    USE SIGNAL ;
    PORT
      LAYER M5 ;
        RECT 42.4320 0.0000 42.4560 0.0840 ;
    END
  END p_hh[21]
  PIN p_hh[22]
    DIRECTION OUTPUT ;
    USE SIGNAL ;
    PORT
      LAYER M5 ;
        RECT 43.9680 0.0000 43.9920 0.0840 ;
    END
  END p_hh[22]
  PIN p_hh[23]
    DIRECTION OUTPUT ;
    USE SIGNAL ;
    PORT
      LAYER M5 ;
        RECT 45.5040 0.0000 45.5280 0.0840 ;
    END
  END p_hh[23]
  PIN p_hh[24]
    DIRECTION OUTPUT ;
    USE SIGNAL ;
    PORT
      LAYER M5 ;
        RECT 47.0400 0.0000 47.0640 0.0840 ;
    END
  END p_hh[24]
  PIN p_hh[25]
    DIRECTION OUTPUT ;
    USE SIGNAL ;
    PORT
      LAYER M5 ;
        RECT 48.5760 0.0000 48.6000 0.0840 ;
    END
  END p_hh[25]
  PIN p_hh[26]
    DIRECTION OUTPUT ;
    USE SIGNAL ;
    PORT
      LAYER M5 ;
        RECT 50.2080 0.0000 50.2320 0.0840 ;
    END
  END p_hh[26]
  PIN p_hh[27]
    DIRECTION OUTPUT ;
    USE SIGNAL ;
    PORT
      LAYER M5 ;
        RECT 51.7440 0.0000 51.7680 0.0840 ;
    END
  END p_hh[27]
  PIN p_hh[28]
    DIRECTION OUTPUT ;
    USE SIGNAL ;
    PORT
      LAYER M5 ;
        RECT 53.2800 0.0000 53.3040 0.0840 ;
    END
  END p_hh[28]
  PIN p_hh[29]
    DIRECTION OUTPUT ;
    USE SIGNAL ;
    PORT
      LAYER M5 ;
        RECT 54.8160 0.0000 54.8400 0.0840 ;
    END
  END p_hh[29]
  PIN p_hh[2]
    DIRECTION OUTPUT ;
    USE SIGNAL ;
    PORT
      LAYER M5 ;
        RECT 12.8640 0.0000 12.8880 0.0840 ;
    END
  END p_hh[2]
  PIN p_hh[30]
    DIRECTION OUTPUT ;
    USE SIGNAL ;
    PORT
      LAYER M5 ;
        RECT 56.4480 0.0000 56.4720 0.0840 ;
    END
  END p_hh[30]
  PIN p_hh[31]
    DIRECTION OUTPUT ;
    USE SIGNAL ;
    PORT
      LAYER M5 ;
        RECT 57.9840 0.0000 58.0080 0.0840 ;
    END
  END p_hh[31]
  PIN p_hh[3]
    DIRECTION OUTPUT ;
    USE SIGNAL ;
    PORT
      LAYER M5 ;
        RECT 14.4000 0.0000 14.4240 0.0840 ;
    END
  END p_hh[3]
  PIN p_hh[4]
    DIRECTION OUTPUT ;
    USE SIGNAL ;
    PORT
      LAYER M5 ;
        RECT 15.9360 0.0000 15.9600 0.0840 ;
    END
  END p_hh[4]
  PIN p_hh[5]
    DIRECTION OUTPUT ;
    USE SIGNAL ;
    PORT
      LAYER M5 ;
        RECT 17.4720 0.0000 17.4960 0.0840 ;
    END
  END p_hh[5]
  PIN p_hh[6]
    DIRECTION OUTPUT ;
    USE SIGNAL ;
    PORT
      LAYER M5 ;
        RECT 19.1040 0.0000 19.1280 0.0840 ;
    END
  END p_hh[6]
  PIN p_hh[7]
    DIRECTION OUTPUT ;
    USE SIGNAL ;
    PORT
      LAYER M5 ;
        RECT 20.6400 0.0000 20.6640 0.0840 ;
    END
  END p_hh[7]
  PIN p_hh[8]
    DIRECTION OUTPUT ;
    USE SIGNAL ;
    PORT
      LAYER M5 ;
        RECT 22.1760 0.0000 22.2000 0.0840 ;
    END
  END p_hh[8]
  PIN p_hh[9]
    DIRECTION OUTPUT ;
    USE SIGNAL ;
    PORT
      LAYER M5 ;
        RECT 23.7120 0.0000 23.7360 0.0840 ;
    END
  END p_hh[9]
  PIN p_kk[0]
    DIRECTION OUTPUT ;
    USE SIGNAL ;
    PORT
      LAYER M5 ;
        RECT 59.5200 0.0000 59.5440 0.0840 ;
    END
  END p_kk[0]
  PIN p_kk[10]
    DIRECTION OUTPUT ;
    USE SIGNAL ;
    PORT
      LAYER M5 ;
        RECT 75.0720 0.0000 75.0960 0.0840 ;
    END
  END p_kk[10]
  PIN p_kk[11]
    DIRECTION OUTPUT ;
    USE SIGNAL ;
    PORT
      LAYER M5 ;
        RECT 76.6080 0.0000 76.6320 0.0840 ;
    END
  END p_kk[11]
  PIN p_kk[12]
    DIRECTION OUTPUT ;
    USE SIGNAL ;
    PORT
      LAYER M5 ;
        RECT 78.1440 0.0000 78.1680 0.0840 ;
    END
  END p_kk[12]
  PIN p_kk[13]
    DIRECTION OUTPUT ;
    USE SIGNAL ;
    PORT
      LAYER M5 ;
        RECT 79.6800 0.0000 79.7040 0.0840 ;
    END
  END p_kk[13]
  PIN p_kk[14]
    DIRECTION OUTPUT ;
    USE SIGNAL ;
    PORT
      LAYER M5 ;
        RECT 81.3120 0.0000 81.3360 0.0840 ;
    END
  END p_kk[14]
  PIN p_kk[15]
    DIRECTION OUTPUT ;
    USE SIGNAL ;
    PORT
      LAYER M5 ;
        RECT 82.8480 0.0000 82.8720 0.0840 ;
    END
  END p_kk[15]
  PIN p_kk[16]
    DIRECTION OUTPUT ;
    USE SIGNAL ;
    PORT
      LAYER M5 ;
        RECT 84.3840 0.0000 84.4080 0.0840 ;
    END
  END p_kk[16]
  PIN p_kk[17]
    DIRECTION OUTPUT ;
    USE SIGNAL ;
    PORT
      LAYER M5 ;
        RECT 85.9200 0.0000 85.9440 0.0840 ;
    END
  END p_kk[17]
  PIN p_kk[18]
    DIRECTION OUTPUT ;
    USE SIGNAL ;
    PORT
      LAYER M5 ;
        RECT 87.5520 0.0000 87.5760 0.0840 ;
    END
  END p_kk[18]
  PIN p_kk[19]
    DIRECTION OUTPUT ;
    USE SIGNAL ;
    PORT
      LAYER M5 ;
        RECT 89.0880 0.0000 89.1120 0.0840 ;
    END
  END p_kk[19]
  PIN p_kk[1]
    DIRECTION OUTPUT ;
    USE SIGNAL ;
    PORT
      LAYER M5 ;
        RECT 61.0560 0.0000 61.0800 0.0840 ;
    END
  END p_kk[1]
  PIN p_kk[20]
    DIRECTION OUTPUT ;
    USE SIGNAL ;
    PORT
      LAYER M5 ;
        RECT 90.6240 0.0000 90.6480 0.0840 ;
    END
  END p_kk[20]
  PIN p_kk[21]
    DIRECTION OUTPUT ;
    USE SIGNAL ;
    PORT
      LAYER M5 ;
        RECT 92.1600 0.0000 92.1840 0.0840 ;
    END
  END p_kk[21]
  PIN p_kk[22]
    DIRECTION OUTPUT ;
    USE SIGNAL ;
    PORT
      LAYER M5 ;
        RECT 93.6960 0.0000 93.7200 0.0840 ;
    END
  END p_kk[22]
  PIN p_kk[23]
    DIRECTION OUTPUT ;
    USE SIGNAL ;
    PORT
      LAYER M5 ;
        RECT 95.2320 0.0000 95.2560 0.0840 ;
    END
  END p_kk[23]
  PIN p_kk[24]
    DIRECTION OUTPUT ;
    USE SIGNAL ;
    PORT
      LAYER M5 ;
        RECT 96.8640 0.0000 96.8880 0.0840 ;
    END
  END p_kk[24]
  PIN p_kk[25]
    DIRECTION OUTPUT ;
    USE SIGNAL ;
    PORT
      LAYER M5 ;
        RECT 98.4000 0.0000 98.4240 0.0840 ;
    END
  END p_kk[25]
  PIN p_kk[26]
    DIRECTION OUTPUT ;
    USE SIGNAL ;
    PORT
      LAYER M5 ;
        RECT 99.9360 0.0000 99.9600 0.0840 ;
    END
  END p_kk[26]
  PIN p_kk[27]
    DIRECTION OUTPUT ;
    USE SIGNAL ;
    PORT
      LAYER M5 ;
        RECT 101.4720 0.0000 101.4960 0.0840 ;
    END
  END p_kk[27]
  PIN p_kk[28]
    DIRECTION OUTPUT ;
    USE SIGNAL ;
    PORT
      LAYER M5 ;
        RECT 103.1040 0.0000 103.1280 0.0840 ;
    END
  END p_kk[28]
  PIN p_kk[29]
    DIRECTION OUTPUT ;
    USE SIGNAL ;
    PORT
      LAYER M5 ;
        RECT 104.6400 0.0000 104.6640 0.0840 ;
    END
  END p_kk[29]
  PIN p_kk[2]
    DIRECTION OUTPUT ;
    USE SIGNAL ;
    PORT
      LAYER M5 ;
        RECT 62.5920 0.0000 62.6160 0.0840 ;
    END
  END p_kk[2]
  PIN p_kk[30]
    DIRECTION OUTPUT ;
    USE SIGNAL ;
    PORT
      LAYER M5 ;
        RECT 106.1760 0.0000 106.2000 0.0840 ;
    END
  END p_kk[30]
  PIN p_kk[31]
    DIRECTION OUTPUT ;
    USE SIGNAL ;
    PORT
      LAYER M5 ;
        RECT 107.7120 0.0000 107.7360 0.0840 ;
    END
  END p_kk[31]
  PIN p_kk[3]
    DIRECTION OUTPUT ;
    USE SIGNAL ;
    PORT
      LAYER M5 ;
        RECT 64.1280 0.0000 64.1520 0.0840 ;
    END
  END p_kk[3]
  PIN p_kk[4]
    DIRECTION OUTPUT ;
    USE SIGNAL ;
    PORT
      LAYER M5 ;
        RECT 65.7600 0.0000 65.7840 0.0840 ;
    END
  END p_kk[4]
  PIN p_kk[5]
    DIRECTION OUTPUT ;
    USE SIGNAL ;
    PORT
      LAYER M5 ;
        RECT 67.2960 0.0000 67.3200 0.0840 ;
    END
  END p_kk[5]
  PIN p_kk[6]
    DIRECTION OUTPUT ;
    USE SIGNAL ;
    PORT
      LAYER M5 ;
        RECT 68.8320 0.0000 68.8560 0.0840 ;
    END
  END p_kk[6]
  PIN p_kk[7]
    DIRECTION OUTPUT ;
    USE SIGNAL ;
    PORT
      LAYER M5 ;
        RECT 70.3680 0.0000 70.3920 0.0840 ;
    END
  END p_kk[7]
  PIN p_kk[8]
    DIRECTION OUTPUT ;
    USE SIGNAL ;
    PORT
      LAYER M5 ;
        RECT 72.0000 0.0000 72.0240 0.0840 ;
    END
  END p_kk[8]
  PIN p_kk[9]
    DIRECTION OUTPUT ;
    USE SIGNAL ;
    PORT
      LAYER M5 ;
        RECT 73.5360 0.0000 73.5600 0.0840 ;
    END
  END p_kk[9]
  PIN p_v
    DIRECTION OUTPUT ;
    USE SIGNAL ;
    PORT
      LAYER M5 ;
        RECT 5.0880 0.0000 5.1120 0.0840 ;
    END
  END p_v
  PIN rst_n
    DIRECTION INPUT ;
    USE SIGNAL ;
    PORT
      LAYER M4 ;
        RECT 172.716000 173.184000 172.800000 173.208000 ;
    END
  END rst_n
  PIN VSS
    DIRECTION INOUT ;
    USE GROUND ;
    PORT
      LAYER M5 ;
        RECT 6.324000 4.320000 6.444000 341.280000 ;
        RECT 10.644000 4.320000 10.764000 341.280000 ;
        RECT 14.964000 4.320000 15.084000 341.280000 ;
        RECT 19.284000 4.320000 19.404000 341.280000 ;
        RECT 23.604000 4.320000 23.724000 341.280000 ;
        RECT 27.924000 4.320000 28.044000 341.280000 ;
        RECT 32.244000 4.320000 32.364000 341.280000 ;
        RECT 36.564000 4.320000 36.684000 341.280000 ;
        RECT 40.884000 4.320000 41.004000 341.280000 ;
        RECT 45.204000 4.320000 45.324000 341.280000 ;
        RECT 49.524000 4.320000 49.644000 341.280000 ;
        RECT 53.844000 4.320000 53.964000 341.280000 ;
        RECT 58.164000 4.320000 58.284000 341.280000 ;
        RECT 62.484000 4.320000 62.604000 341.280000 ;
        RECT 66.804000 4.320000 66.924000 341.280000 ;
        RECT 71.124000 4.320000 71.244000 341.280000 ;
        RECT 75.444000 4.320000 75.564000 341.280000 ;
        RECT 79.764000 4.320000 79.884000 341.280000 ;
        RECT 84.084000 4.320000 84.204000 341.280000 ;
        RECT 88.404000 4.320000 88.524000 341.280000 ;
        RECT 92.724000 4.320000 92.844000 341.280000 ;
        RECT 97.044000 4.320000 97.164000 341.280000 ;
        RECT 101.364000 4.320000 101.484000 341.280000 ;
        RECT 105.684000 4.320000 105.804000 341.280000 ;
        RECT 110.004000 4.320000 110.124000 341.280000 ;
        RECT 114.324000 4.320000 114.444000 341.280000 ;
        RECT 118.644000 4.320000 118.764000 341.280000 ;
        RECT 122.964000 4.320000 123.084000 341.280000 ;
        RECT 127.284000 4.320000 127.404000 341.280000 ;
        RECT 131.604000 4.320000 131.724000 341.280000 ;
        RECT 135.924000 4.320000 136.044000 341.280000 ;
        RECT 140.244000 4.320000 140.364000 341.280000 ;
        RECT 144.564000 4.320000 144.684000 341.280000 ;
        RECT 148.884000 4.320000 149.004000 341.280000 ;
        RECT 153.204000 4.320000 153.324000 341.280000 ;
        RECT 157.524000 4.320000 157.644000 341.280000 ;
        RECT 161.844000 4.320000 161.964000 341.280000 ;
        RECT 166.164000 4.320000 166.284000 341.280000 ;
    END
  END VSS
  PIN VDD
    DIRECTION INOUT ;
    USE POWER ;
    PORT
      LAYER M5 ;
        RECT 6.516000 4.320000 6.636000 341.280000 ;
        RECT 10.836000 4.320000 10.956000 341.280000 ;
        RECT 15.156000 4.320000 15.276000 341.280000 ;
        RECT 19.476000 4.320000 19.596000 341.280000 ;
        RECT 23.796000 4.320000 23.916000 341.280000 ;
        RECT 28.116000 4.320000 28.236000 341.280000 ;
        RECT 32.436000 4.320000 32.556000 341.280000 ;
        RECT 36.756000 4.320000 36.876000 341.280000 ;
        RECT 41.076000 4.320000 41.196000 341.280000 ;
        RECT 45.396000 4.320000 45.516000 341.280000 ;
        RECT 49.716000 4.320000 49.836000 341.280000 ;
        RECT 54.036000 4.320000 54.156000 341.280000 ;
        RECT 58.356000 4.320000 58.476000 341.280000 ;
        RECT 62.676000 4.320000 62.796000 341.280000 ;
        RECT 66.996000 4.320000 67.116000 341.280000 ;
        RECT 71.316000 4.320000 71.436000 341.280000 ;
        RECT 75.636000 4.320000 75.756000 341.280000 ;
        RECT 79.956000 4.320000 80.076000 341.280000 ;
        RECT 84.276000 4.320000 84.396000 341.280000 ;
        RECT 88.596000 4.320000 88.716000 341.280000 ;
        RECT 92.916000 4.320000 93.036000 341.280000 ;
        RECT 97.236000 4.320000 97.356000 341.280000 ;
        RECT 101.556000 4.320000 101.676000 341.280000 ;
        RECT 105.876000 4.320000 105.996000 341.280000 ;
        RECT 110.196000 4.320000 110.316000 341.280000 ;
        RECT 114.516000 4.320000 114.636000 341.280000 ;
        RECT 118.836000 4.320000 118.956000 341.280000 ;
        RECT 123.156000 4.320000 123.276000 341.280000 ;
        RECT 127.476000 4.320000 127.596000 341.280000 ;
        RECT 131.796000 4.320000 131.916000 341.280000 ;
        RECT 136.116000 4.320000 136.236000 341.280000 ;
        RECT 140.436000 4.320000 140.556000 341.280000 ;
        RECT 144.756000 4.320000 144.876000 341.280000 ;
        RECT 149.076000 4.320000 149.196000 341.280000 ;
        RECT 153.396000 4.320000 153.516000 341.280000 ;
        RECT 157.716000 4.320000 157.836000 341.280000 ;
        RECT 162.036000 4.320000 162.156000 341.280000 ;
        RECT 166.356000 4.320000 166.476000 341.280000 ;
    END
  END VDD
  OBS
    LAYER M1 ;
      RECT 0.000000 0.000000 172.800000 345.600000 ;
    LAYER M2 ;
      RECT 0.000000 0.000000 172.800000 345.600000 ;
    LAYER M3 ;
      RECT 0.000000 0.000000 172.800000 345.600000 ;
    LAYER M4 ;
      RECT 0.000000 0.000000 172.800000 345.600000 ;
    LAYER M5 ;
      RECT 0.000000 0.000000 172.800000 345.600000 ;
    LAYER M6 ;
      RECT 0.000000 0.000000 172.800000 170.640000 ;
      RECT 0.000000 174.960000 172.800000 345.600000 ;
      RECT 0.000000 170.640000 79.920000 174.960000 ;
      RECT 84.240000 170.640000 172.800000 174.960000 ;
    LAYER M7 ;
      RECT 0.000000 0.000000 172.800000 170.640000 ;
      RECT 0.000000 174.960000 172.800000 345.600000 ;
      RECT 0.000000 170.640000 79.920000 174.960000 ;
      RECT 84.240000 170.640000 172.800000 174.960000 ;
  END
END ot_s81sl_ve_s
END LIBRARY
